VERSION 5.8 ;
BUSBITCHARS "[]" ;
DIVIDERCHAR "/" ;
UNITS
    DATABASE MICRONS 1000 ;
END UNITS

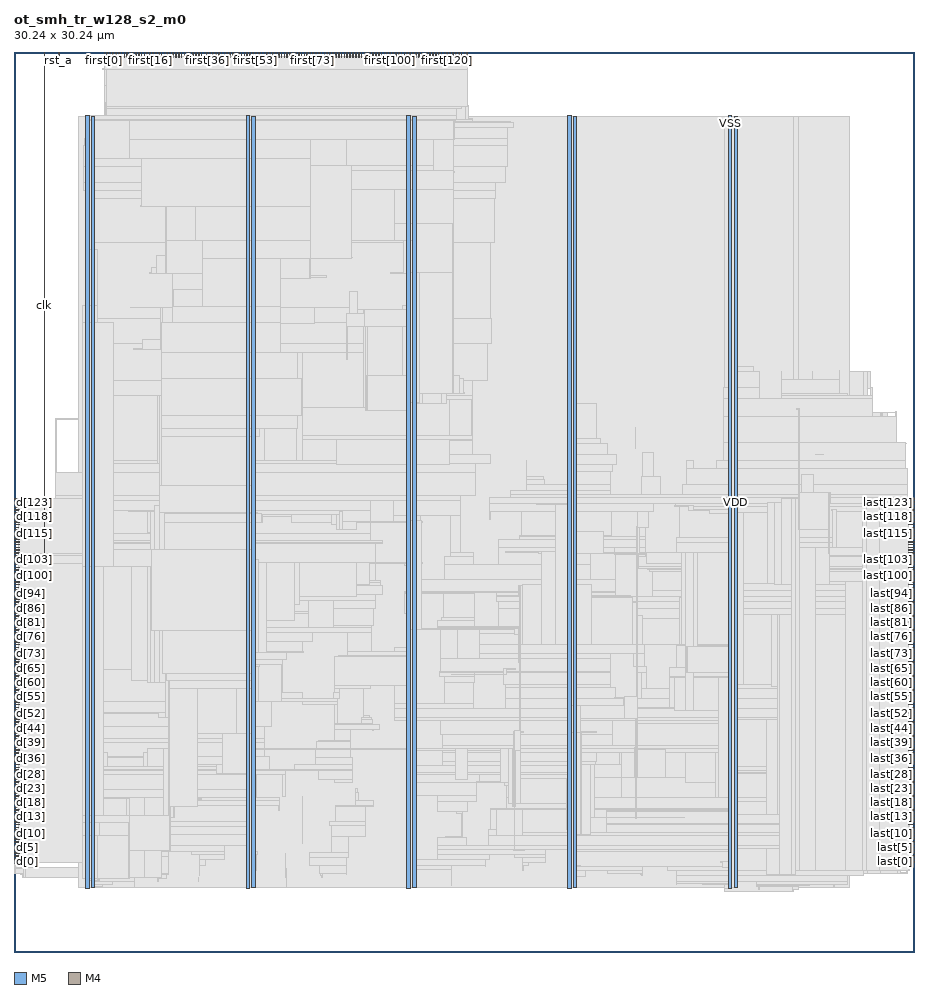
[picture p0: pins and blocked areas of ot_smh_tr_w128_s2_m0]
MACRO ot_smh_tr_w128_s2_m0
  FOREIGN ot_smh_tr_w128_s2_m0 0 0 ;
  CLASS BLOCK ;
  SIZE 30.24 BY 30.24 ;
  PIN clk
    DIRECTION INPUT ;
    USE SIGNAL ;
    PORT
      LAYER M5 ;
        RECT  1.008 30.048 1.032 30.24 ;
    END
    PORT
      LAYER M5 ;
        RECT  1.008 13.379 1.032 30.096 ;
    END
  END clk
  PIN d[0]
    DIRECTION INPUT ;
    USE SIGNAL ;
    PORT
      LAYER M4 ;
        RECT  0 3.024 0.192 3.048 ;
    END
  END d[0]
  PIN d[100]
    DIRECTION INPUT ;
    USE SIGNAL ;
    PORT
      LAYER M4 ;
        RECT  0 12.624 0.192 12.648 ;
    END
  END d[100]
  PIN d[101]
    DIRECTION INPUT ;
    USE SIGNAL ;
    PORT
      LAYER M4 ;
        RECT  0 12.72 0.192 12.744 ;
    END
  END d[101]
  PIN d[102]
    DIRECTION INPUT ;
    USE SIGNAL ;
    PORT
      LAYER M4 ;
        RECT  0 12.816 0.192 12.84 ;
    END
  END d[102]
  PIN d[103]
    DIRECTION INPUT ;
    USE SIGNAL ;
    PORT
      LAYER M4 ;
        RECT  0 12.912 0.192 12.936 ;
    END
  END d[103]
  PIN d[104]
    DIRECTION INPUT ;
    USE SIGNAL ;
    PORT
      LAYER M4 ;
        RECT  0 13.008 0.192 13.032 ;
    END
  END d[104]
  PIN d[105]
    DIRECTION INPUT ;
    USE SIGNAL ;
    PORT
      LAYER M4 ;
        RECT  0 13.104 0.192 13.128 ;
    END
  END d[105]
  PIN d[106]
    DIRECTION INPUT ;
    USE SIGNAL ;
    PORT
      LAYER M4 ;
        RECT  0 13.2 0.192 13.224 ;
    END
  END d[106]
  PIN d[107]
    DIRECTION INPUT ;
    USE SIGNAL ;
    PORT
      LAYER M4 ;
        RECT  0 13.296 0.192 13.32 ;
    END
  END d[107]
  PIN d[108]
    DIRECTION INPUT ;
    USE SIGNAL ;
    PORT
      LAYER M4 ;
        RECT  0 13.392 0.192 13.416 ;
    END
  END d[108]
  PIN d[109]
    DIRECTION INPUT ;
    USE SIGNAL ;
    PORT
      LAYER M4 ;
        RECT  0 13.488 0.192 13.512 ;
    END
  END d[109]
  PIN d[10]
    DIRECTION INPUT ;
    USE SIGNAL ;
    PORT
      LAYER M4 ;
        RECT  0 3.984 0.192 4.008 ;
    END
  END d[10]
  PIN d[110]
    DIRECTION INPUT ;
    USE SIGNAL ;
    PORT
      LAYER M4 ;
        RECT  0 13.584 0.192 13.608 ;
    END
  END d[110]
  PIN d[111]
    DIRECTION INPUT ;
    USE SIGNAL ;
    PORT
      LAYER M4 ;
        RECT  0 13.68 0.192 13.704 ;
    END
  END d[111]
  PIN d[112]
    DIRECTION INPUT ;
    USE SIGNAL ;
    PORT
      LAYER M4 ;
        RECT  0 13.776 0.192 13.8 ;
    END
  END d[112]
  PIN d[113]
    DIRECTION INPUT ;
    USE SIGNAL ;
    PORT
      LAYER M4 ;
        RECT  0 13.872 0.192 13.896 ;
    END
  END d[113]
  PIN d[114]
    DIRECTION INPUT ;
    USE SIGNAL ;
    PORT
      LAYER M4 ;
        RECT  0 13.968 0.192 13.992 ;
    END
  END d[114]
  PIN d[115]
    DIRECTION INPUT ;
    USE SIGNAL ;
    PORT
      LAYER M4 ;
        RECT  0 14.064 0.192 14.088 ;
    END
  END d[115]
  PIN d[116]
    DIRECTION INPUT ;
    USE SIGNAL ;
    PORT
      LAYER M4 ;
        RECT  0 14.16 0.192 14.184 ;
    END
  END d[116]
  PIN d[117]
    DIRECTION INPUT ;
    USE SIGNAL ;
    PORT
      LAYER M4 ;
        RECT  0 14.256 0.192 14.28 ;
    END
  END d[117]
  PIN d[118]
    DIRECTION INPUT ;
    USE SIGNAL ;
    PORT
      LAYER M4 ;
        RECT  0 14.352 0.192 14.376 ;
    END
  END d[118]
  PIN d[119]
    DIRECTION INPUT ;
    USE SIGNAL ;
    PORT
      LAYER M4 ;
        RECT  0 14.448 0.192 14.472 ;
    END
  END d[119]
  PIN d[11]
    DIRECTION INPUT ;
    USE SIGNAL ;
    PORT
      LAYER M4 ;
        RECT  0 4.08 0.192 4.104 ;
    END
  END d[11]
  PIN d[120]
    DIRECTION INPUT ;
    USE SIGNAL ;
    PORT
      LAYER M4 ;
        RECT  0 14.544 0.192 14.568 ;
    END
  END d[120]
  PIN d[121]
    DIRECTION INPUT ;
    USE SIGNAL ;
    PORT
      LAYER M4 ;
        RECT  0 14.64 0.192 14.664 ;
    END
  END d[121]
  PIN d[122]
    DIRECTION INPUT ;
    USE SIGNAL ;
    PORT
      LAYER M4 ;
        RECT  0 14.736 0.192 14.76 ;
    END
  END d[122]
  PIN d[123]
    DIRECTION INPUT ;
    USE SIGNAL ;
    PORT
      LAYER M4 ;
        RECT  0 14.832 0.192 14.856 ;
    END
  END d[123]
  PIN d[124]
    DIRECTION INPUT ;
    USE SIGNAL ;
    PORT
      LAYER M4 ;
        RECT  0 14.928 0.192 14.952 ;
    END
  END d[124]
  PIN d[125]
    DIRECTION INPUT ;
    USE SIGNAL ;
    PORT
      LAYER M4 ;
        RECT  0 15.024 0.192 15.048 ;
    END
  END d[125]
  PIN d[126]
    DIRECTION INPUT ;
    USE SIGNAL ;
    PORT
      LAYER M4 ;
        RECT  0 15.12 0.192 15.144 ;
    END
  END d[126]
  PIN d[127]
    DIRECTION INPUT ;
    USE SIGNAL ;
    PORT
      LAYER M4 ;
        RECT  0 15.216 0.192 15.24 ;
    END
  END d[127]
  PIN d[12]
    DIRECTION INPUT ;
    USE SIGNAL ;
    PORT
      LAYER M4 ;
        RECT  0 4.176 0.192 4.2 ;
    END
  END d[12]
  PIN d[13]
    DIRECTION INPUT ;
    USE SIGNAL ;
    PORT
      LAYER M4 ;
        RECT  0 4.272 0.192 4.296 ;
    END
  END d[13]
  PIN d[14]
    DIRECTION INPUT ;
    USE SIGNAL ;
    PORT
      LAYER M4 ;
        RECT  0 4.368 0.192 4.392 ;
    END
  END d[14]
  PIN d[15]
    DIRECTION INPUT ;
    USE SIGNAL ;
    PORT
      LAYER M4 ;
        RECT  0 4.464 0.192 4.488 ;
    END
  END d[15]
  PIN d[16]
    DIRECTION INPUT ;
    USE SIGNAL ;
    PORT
      LAYER M4 ;
        RECT  0 4.56 0.192 4.584 ;
    END
  END d[16]
  PIN d[17]
    DIRECTION INPUT ;
    USE SIGNAL ;
    PORT
      LAYER M4 ;
        RECT  0 4.656 0.192 4.68 ;
    END
  END d[17]
  PIN d[18]
    DIRECTION INPUT ;
    USE SIGNAL ;
    PORT
      LAYER M4 ;
        RECT  0 4.752 0.192 4.776 ;
    END
  END d[18]
  PIN d[19]
    DIRECTION INPUT ;
    USE SIGNAL ;
    PORT
      LAYER M4 ;
        RECT  0 4.848 0.192 4.872 ;
    END
  END d[19]
  PIN d[1]
    DIRECTION INPUT ;
    USE SIGNAL ;
    PORT
      LAYER M4 ;
        RECT  0 3.12 0.192 3.144 ;
    END
  END d[1]
  PIN d[20]
    DIRECTION INPUT ;
    USE SIGNAL ;
    PORT
      LAYER M4 ;
        RECT  0 4.944 0.192 4.968 ;
    END
  END d[20]
  PIN d[21]
    DIRECTION INPUT ;
    USE SIGNAL ;
    PORT
      LAYER M4 ;
        RECT  0 5.04 0.192 5.064 ;
    END
  END d[21]
  PIN d[22]
    DIRECTION INPUT ;
    USE SIGNAL ;
    PORT
      LAYER M4 ;
        RECT  0 5.136 0.192 5.16 ;
    END
  END d[22]
  PIN d[23]
    DIRECTION INPUT ;
    USE SIGNAL ;
    PORT
      LAYER M4 ;
        RECT  0 5.232 0.192 5.256 ;
    END
  END d[23]
  PIN d[24]
    DIRECTION INPUT ;
    USE SIGNAL ;
    PORT
      LAYER M4 ;
        RECT  0 5.328 0.192 5.352 ;
    END
  END d[24]
  PIN d[25]
    DIRECTION INPUT ;
    USE SIGNAL ;
    PORT
      LAYER M4 ;
        RECT  0 5.424 0.192 5.448 ;
    END
  END d[25]
  PIN d[26]
    DIRECTION INPUT ;
    USE SIGNAL ;
    PORT
      LAYER M4 ;
        RECT  0 5.52 0.192 5.544 ;
    END
  END d[26]
  PIN d[27]
    DIRECTION INPUT ;
    USE SIGNAL ;
    PORT
      LAYER M4 ;
        RECT  0 5.616 0.192 5.64 ;
    END
  END d[27]
  PIN d[28]
    DIRECTION INPUT ;
    USE SIGNAL ;
    PORT
      LAYER M4 ;
        RECT  0 5.712 0.192 5.736 ;
    END
  END d[28]
  PIN d[29]
    DIRECTION INPUT ;
    USE SIGNAL ;
    PORT
      LAYER M4 ;
        RECT  0 5.808 0.192 5.832 ;
    END
  END d[29]
  PIN d[2]
    DIRECTION INPUT ;
    USE SIGNAL ;
    PORT
      LAYER M4 ;
        RECT  0 3.216 0.192 3.24 ;
    END
  END d[2]
  PIN d[30]
    DIRECTION INPUT ;
    USE SIGNAL ;
    PORT
      LAYER M4 ;
        RECT  0 5.904 0.192 5.928 ;
    END
  END d[30]
  PIN d[31]
    DIRECTION INPUT ;
    USE SIGNAL ;
    PORT
      LAYER M4 ;
        RECT  0 6 0.192 6.024 ;
    END
  END d[31]
  PIN d[32]
    DIRECTION INPUT ;
    USE SIGNAL ;
    PORT
      LAYER M4 ;
        RECT  0 6.096 0.192 6.12 ;
    END
  END d[32]
  PIN d[33]
    DIRECTION INPUT ;
    USE SIGNAL ;
    PORT
      LAYER M4 ;
        RECT  0 6.192 0.192 6.216 ;
    END
  END d[33]
  PIN d[34]
    DIRECTION INPUT ;
    USE SIGNAL ;
    PORT
      LAYER M4 ;
        RECT  0 6.288 0.192 6.312 ;
    END
  END d[34]
  PIN d[35]
    DIRECTION INPUT ;
    USE SIGNAL ;
    PORT
      LAYER M4 ;
        RECT  0 6.384 0.192 6.408 ;
    END
  END d[35]
  PIN d[36]
    DIRECTION INPUT ;
    USE SIGNAL ;
    PORT
      LAYER M4 ;
        RECT  0 6.48 0.192 6.504 ;
    END
  END d[36]
  PIN d[37]
    DIRECTION INPUT ;
    USE SIGNAL ;
    PORT
      LAYER M4 ;
        RECT  0 6.576 0.192 6.6 ;
    END
  END d[37]
  PIN d[38]
    DIRECTION INPUT ;
    USE SIGNAL ;
    PORT
      LAYER M4 ;
        RECT  0 6.672 0.192 6.696 ;
    END
  END d[38]
  PIN d[39]
    DIRECTION INPUT ;
    USE SIGNAL ;
    PORT
      LAYER M4 ;
        RECT  0 6.768 0.192 6.792 ;
    END
  END d[39]
  PIN d[3]
    DIRECTION INPUT ;
    USE SIGNAL ;
    PORT
      LAYER M4 ;
        RECT  0 3.312 0.192 3.336 ;
    END
  END d[3]
  PIN d[40]
    DIRECTION INPUT ;
    USE SIGNAL ;
    PORT
      LAYER M4 ;
        RECT  0 6.864 0.192 6.888 ;
    END
  END d[40]
  PIN d[41]
    DIRECTION INPUT ;
    USE SIGNAL ;
    PORT
      LAYER M4 ;
        RECT  0 6.96 0.192 6.984 ;
    END
  END d[41]
  PIN d[42]
    DIRECTION INPUT ;
    USE SIGNAL ;
    PORT
      LAYER M4 ;
        RECT  0 7.056 0.192 7.08 ;
    END
  END d[42]
  PIN d[43]
    DIRECTION INPUT ;
    USE SIGNAL ;
    PORT
      LAYER M4 ;
        RECT  0 7.152 0.192 7.176 ;
    END
  END d[43]
  PIN d[44]
    DIRECTION INPUT ;
    USE SIGNAL ;
    PORT
      LAYER M4 ;
        RECT  0 7.248 0.192 7.272 ;
    END
  END d[44]
  PIN d[45]
    DIRECTION INPUT ;
    USE SIGNAL ;
    PORT
      LAYER M4 ;
        RECT  0 7.344 0.192 7.368 ;
    END
  END d[45]
  PIN d[46]
    DIRECTION INPUT ;
    USE SIGNAL ;
    PORT
      LAYER M4 ;
        RECT  0 7.44 0.192 7.464 ;
    END
  END d[46]
  PIN d[47]
    DIRECTION INPUT ;
    USE SIGNAL ;
    PORT
      LAYER M4 ;
        RECT  0 7.536 0.192 7.56 ;
    END
  END d[47]
  PIN d[48]
    DIRECTION INPUT ;
    USE SIGNAL ;
    PORT
      LAYER M4 ;
        RECT  0 7.632 0.192 7.656 ;
    END
  END d[48]
  PIN d[49]
    DIRECTION INPUT ;
    USE SIGNAL ;
    PORT
      LAYER M4 ;
        RECT  0 7.728 0.192 7.752 ;
    END
  END d[49]
  PIN d[4]
    DIRECTION INPUT ;
    USE SIGNAL ;
    PORT
      LAYER M4 ;
        RECT  0 3.408 0.192 3.432 ;
    END
  END d[4]
  PIN d[50]
    DIRECTION INPUT ;
    USE SIGNAL ;
    PORT
      LAYER M4 ;
        RECT  0 7.824 0.192 7.848 ;
    END
  END d[50]
  PIN d[51]
    DIRECTION INPUT ;
    USE SIGNAL ;
    PORT
      LAYER M4 ;
        RECT  0 7.92 0.192 7.944 ;
    END
  END d[51]
  PIN d[52]
    DIRECTION INPUT ;
    USE SIGNAL ;
    PORT
      LAYER M4 ;
        RECT  0 8.016 0.192 8.04 ;
    END
  END d[52]
  PIN d[53]
    DIRECTION INPUT ;
    USE SIGNAL ;
    PORT
      LAYER M4 ;
        RECT  0 8.112 0.192 8.136 ;
    END
  END d[53]
  PIN d[54]
    DIRECTION INPUT ;
    USE SIGNAL ;
    PORT
      LAYER M4 ;
        RECT  0 8.208 0.192 8.232 ;
    END
  END d[54]
  PIN d[55]
    DIRECTION INPUT ;
    USE SIGNAL ;
    PORT
      LAYER M4 ;
        RECT  0 8.304 0.192 8.328 ;
    END
  END d[55]
  PIN d[56]
    DIRECTION INPUT ;
    USE SIGNAL ;
    PORT
      LAYER M4 ;
        RECT  0 8.4 0.192 8.424 ;
    END
  END d[56]
  PIN d[57]
    DIRECTION INPUT ;
    USE SIGNAL ;
    PORT
      LAYER M4 ;
        RECT  0 8.496 0.192 8.52 ;
    END
  END d[57]
  PIN d[58]
    DIRECTION INPUT ;
    USE SIGNAL ;
    PORT
      LAYER M4 ;
        RECT  0 8.592 0.192 8.616 ;
    END
  END d[58]
  PIN d[59]
    DIRECTION INPUT ;
    USE SIGNAL ;
    PORT
      LAYER M4 ;
        RECT  0 8.688 0.192 8.712 ;
    END
  END d[59]
  PIN d[5]
    DIRECTION INPUT ;
    USE SIGNAL ;
    PORT
      LAYER M4 ;
        RECT  0 3.504 0.192 3.528 ;
    END
  END d[5]
  PIN d[60]
    DIRECTION INPUT ;
    USE SIGNAL ;
    PORT
      LAYER M4 ;
        RECT  0 8.784 0.192 8.808 ;
    END
  END d[60]
  PIN d[61]
    DIRECTION INPUT ;
    USE SIGNAL ;
    PORT
      LAYER M4 ;
        RECT  0 8.88 0.192 8.904 ;
    END
  END d[61]
  PIN d[62]
    DIRECTION INPUT ;
    USE SIGNAL ;
    PORT
      LAYER M4 ;
        RECT  0 8.976 0.192 9 ;
    END
  END d[62]
  PIN d[63]
    DIRECTION INPUT ;
    USE SIGNAL ;
    PORT
      LAYER M4 ;
        RECT  0 9.072 0.192 9.096 ;
    END
  END d[63]
  PIN d[64]
    DIRECTION INPUT ;
    USE SIGNAL ;
    PORT
      LAYER M4 ;
        RECT  0 9.168 0.192 9.192 ;
    END
  END d[64]
  PIN d[65]
    DIRECTION INPUT ;
    USE SIGNAL ;
    PORT
      LAYER M4 ;
        RECT  0 9.264 0.192 9.288 ;
    END
  END d[65]
  PIN d[66]
    DIRECTION INPUT ;
    USE SIGNAL ;
    PORT
      LAYER M4 ;
        RECT  0 9.36 0.192 9.384 ;
    END
  END d[66]
  PIN d[67]
    DIRECTION INPUT ;
    USE SIGNAL ;
    PORT
      LAYER M4 ;
        RECT  0 9.456 0.192 9.48 ;
    END
  END d[67]
  PIN d[68]
    DIRECTION INPUT ;
    USE SIGNAL ;
    PORT
      LAYER M4 ;
        RECT  0 9.552 0.192 9.576 ;
    END
  END d[68]
  PIN d[69]
    DIRECTION INPUT ;
    USE SIGNAL ;
    PORT
      LAYER M4 ;
        RECT  0 9.648 0.192 9.672 ;
    END
  END d[69]
  PIN d[6]
    DIRECTION INPUT ;
    USE SIGNAL ;
    PORT
      LAYER M4 ;
        RECT  0 3.6 0.192 3.624 ;
    END
  END d[6]
  PIN d[70]
    DIRECTION INPUT ;
    USE SIGNAL ;
    PORT
      LAYER M4 ;
        RECT  0 9.744 0.192 9.768 ;
    END
  END d[70]
  PIN d[71]
    DIRECTION INPUT ;
    USE SIGNAL ;
    PORT
      LAYER M4 ;
        RECT  0 9.84 0.192 9.864 ;
    END
  END d[71]
  PIN d[72]
    DIRECTION INPUT ;
    USE SIGNAL ;
    PORT
      LAYER M4 ;
        RECT  0 9.936 0.192 9.96 ;
    END
  END d[72]
  PIN d[73]
    DIRECTION INPUT ;
    USE SIGNAL ;
    PORT
      LAYER M4 ;
        RECT  0 10.032 0.192 10.056 ;
    END
  END d[73]
  PIN d[74]
    DIRECTION INPUT ;
    USE SIGNAL ;
    PORT
      LAYER M4 ;
        RECT  0 10.128 0.192 10.152 ;
    END
  END d[74]
  PIN d[75]
    DIRECTION INPUT ;
    USE SIGNAL ;
    PORT
      LAYER M4 ;
        RECT  0 10.224 0.192 10.248 ;
    END
  END d[75]
  PIN d[76]
    DIRECTION INPUT ;
    USE SIGNAL ;
    PORT
      LAYER M4 ;
        RECT  0 10.32 0.192 10.344 ;
    END
  END d[76]
  PIN d[77]
    DIRECTION INPUT ;
    USE SIGNAL ;
    PORT
      LAYER M4 ;
        RECT  0 10.416 0.192 10.44 ;
    END
  END d[77]
  PIN d[78]
    DIRECTION INPUT ;
    USE SIGNAL ;
    PORT
      LAYER M4 ;
        RECT  0 10.512 0.192 10.536 ;
    END
  END d[78]
  PIN d[79]
    DIRECTION INPUT ;
    USE SIGNAL ;
    PORT
      LAYER M4 ;
        RECT  0 10.608 0.192 10.632 ;
    END
  END d[79]
  PIN d[7]
    DIRECTION INPUT ;
    USE SIGNAL ;
    PORT
      LAYER M4 ;
        RECT  0 3.696 0.192 3.72 ;
    END
  END d[7]
  PIN d[80]
    DIRECTION INPUT ;
    USE SIGNAL ;
    PORT
      LAYER M4 ;
        RECT  0 10.704 0.192 10.728 ;
    END
  END d[80]
  PIN d[81]
    DIRECTION INPUT ;
    USE SIGNAL ;
    PORT
      LAYER M4 ;
        RECT  0 10.8 0.192 10.824 ;
    END
  END d[81]
  PIN d[82]
    DIRECTION INPUT ;
    USE SIGNAL ;
    PORT
      LAYER M4 ;
        RECT  0 10.896 0.192 10.92 ;
    END
  END d[82]
  PIN d[83]
    DIRECTION INPUT ;
    USE SIGNAL ;
    PORT
      LAYER M4 ;
        RECT  0 10.992 0.192 11.016 ;
    END
  END d[83]
  PIN d[84]
    DIRECTION INPUT ;
    USE SIGNAL ;
    PORT
      LAYER M4 ;
        RECT  0 11.088 0.192 11.112 ;
    END
  END d[84]
  PIN d[85]
    DIRECTION INPUT ;
    USE SIGNAL ;
    PORT
      LAYER M4 ;
        RECT  0 11.184 0.192 11.208 ;
    END
  END d[85]
  PIN d[86]
    DIRECTION INPUT ;
    USE SIGNAL ;
    PORT
      LAYER M4 ;
        RECT  0 11.28 0.192 11.304 ;
    END
  END d[86]
  PIN d[87]
    DIRECTION INPUT ;
    USE SIGNAL ;
    PORT
      LAYER M4 ;
        RECT  0 11.376 0.192 11.4 ;
    END
  END d[87]
  PIN d[88]
    DIRECTION INPUT ;
    USE SIGNAL ;
    PORT
      LAYER M4 ;
        RECT  0 11.472 0.192 11.496 ;
    END
  END d[88]
  PIN d[89]
    DIRECTION INPUT ;
    USE SIGNAL ;
    PORT
      LAYER M4 ;
        RECT  0 11.568 0.192 11.592 ;
    END
  END d[89]
  PIN d[8]
    DIRECTION INPUT ;
    USE SIGNAL ;
    PORT
      LAYER M4 ;
        RECT  0 3.792 0.192 3.816 ;
    END
  END d[8]
  PIN d[90]
    DIRECTION INPUT ;
    USE SIGNAL ;
    PORT
      LAYER M4 ;
        RECT  0 11.664 0.192 11.688 ;
    END
  END d[90]
  PIN d[91]
    DIRECTION INPUT ;
    USE SIGNAL ;
    PORT
      LAYER M4 ;
        RECT  0 11.76 0.192 11.784 ;
    END
  END d[91]
  PIN d[92]
    DIRECTION INPUT ;
    USE SIGNAL ;
    PORT
      LAYER M4 ;
        RECT  0 11.856 0.192 11.88 ;
    END
  END d[92]
  PIN d[93]
    DIRECTION INPUT ;
    USE SIGNAL ;
    PORT
      LAYER M4 ;
        RECT  0 11.952 0.192 11.976 ;
    END
  END d[93]
  PIN d[94]
    DIRECTION INPUT ;
    USE SIGNAL ;
    PORT
      LAYER M4 ;
        RECT  0 12.048 0.192 12.072 ;
    END
  END d[94]
  PIN d[95]
    DIRECTION INPUT ;
    USE SIGNAL ;
    PORT
      LAYER M4 ;
        RECT  0 12.144 0.192 12.168 ;
    END
  END d[95]
  PIN d[96]
    DIRECTION INPUT ;
    USE SIGNAL ;
    PORT
      LAYER M4 ;
        RECT  0 12.24 0.192 12.264 ;
    END
  END d[96]
  PIN d[97]
    DIRECTION INPUT ;
    USE SIGNAL ;
    PORT
      LAYER M4 ;
        RECT  0 12.336 0.192 12.36 ;
    END
  END d[97]
  PIN d[98]
    DIRECTION INPUT ;
    USE SIGNAL ;
    PORT
      LAYER M4 ;
        RECT  0 12.432 0.192 12.456 ;
    END
  END d[98]
  PIN d[99]
    DIRECTION INPUT ;
    USE SIGNAL ;
    PORT
      LAYER M4 ;
        RECT  0 12.528 0.192 12.552 ;
    END
  END d[99]
  PIN d[9]
    DIRECTION INPUT ;
    USE SIGNAL ;
    PORT
      LAYER M4 ;
        RECT  0 3.888 0.192 3.912 ;
    END
  END d[9]
  PIN first[0]
    DIRECTION OUTPUT ;
    USE SIGNAL ;
    PORT
      LAYER M5 ;
        RECT  3.024 30.048 3.048 30.24 ;
    END
  END first[0]
  PIN first[100]
    DIRECTION OUTPUT ;
    USE SIGNAL ;
    PORT
      LAYER M5 ;
        RECT  12.624 30.048 12.648 30.24 ;
    END
  END first[100]
  PIN first[101]
    DIRECTION OUTPUT ;
    USE SIGNAL ;
    PORT
      LAYER M5 ;
        RECT  12.72 30.048 12.744 30.24 ;
    END
  END first[101]
  PIN first[102]
    DIRECTION OUTPUT ;
    USE SIGNAL ;
    PORT
      LAYER M5 ;
        RECT  12.816 30.048 12.84 30.24 ;
    END
  END first[102]
  PIN first[103]
    DIRECTION OUTPUT ;
    USE SIGNAL ;
    PORT
      LAYER M5 ;
        RECT  12.912 30.048 12.936 30.24 ;
    END
  END first[103]
  PIN first[104]
    DIRECTION OUTPUT ;
    USE SIGNAL ;
    PORT
      LAYER M5 ;
        RECT  13.008 30.048 13.032 30.24 ;
    END
  END first[104]
  PIN first[105]
    DIRECTION OUTPUT ;
    USE SIGNAL ;
    PORT
      LAYER M5 ;
        RECT  13.104 30.048 13.128 30.24 ;
    END
  END first[105]
  PIN first[106]
    DIRECTION OUTPUT ;
    USE SIGNAL ;
    PORT
      LAYER M5 ;
        RECT  13.2 30.048 13.224 30.24 ;
    END
  END first[106]
  PIN first[107]
    DIRECTION OUTPUT ;
    USE SIGNAL ;
    PORT
      LAYER M5 ;
        RECT  13.296 30.048 13.32 30.24 ;
    END
  END first[107]
  PIN first[108]
    DIRECTION OUTPUT ;
    USE SIGNAL ;
    PORT
      LAYER M5 ;
        RECT  13.392 30.048 13.416 30.24 ;
    END
  END first[108]
  PIN first[109]
    DIRECTION OUTPUT ;
    USE SIGNAL ;
    PORT
      LAYER M5 ;
        RECT  13.488 30.048 13.512 30.24 ;
    END
  END first[109]
  PIN first[10]
    DIRECTION OUTPUT ;
    USE SIGNAL ;
    PORT
      LAYER M5 ;
        RECT  3.984 30.048 4.008 30.24 ;
    END
  END first[10]
  PIN first[110]
    DIRECTION OUTPUT ;
    USE SIGNAL ;
    PORT
      LAYER M5 ;
        RECT  13.584 30.048 13.608 30.24 ;
    END
  END first[110]
  PIN first[111]
    DIRECTION OUTPUT ;
    USE SIGNAL ;
    PORT
      LAYER M5 ;
        RECT  13.68 30.048 13.704 30.24 ;
    END
  END first[111]
  PIN first[112]
    DIRECTION OUTPUT ;
    USE SIGNAL ;
    PORT
      LAYER M5 ;
        RECT  13.776 30.048 13.8 30.24 ;
    END
  END first[112]
  PIN first[113]
    DIRECTION OUTPUT ;
    USE SIGNAL ;
    PORT
      LAYER M5 ;
        RECT  13.872 30.048 13.896 30.24 ;
    END
  END first[113]
  PIN first[114]
    DIRECTION OUTPUT ;
    USE SIGNAL ;
    PORT
      LAYER M5 ;
        RECT  13.968 30.048 13.992 30.24 ;
    END
  END first[114]
  PIN first[115]
    DIRECTION OUTPUT ;
    USE SIGNAL ;
    PORT
      LAYER M5 ;
        RECT  14.064 30.048 14.088 30.24 ;
    END
  END first[115]
  PIN first[116]
    DIRECTION OUTPUT ;
    USE SIGNAL ;
    PORT
      LAYER M5 ;
        RECT  14.16 30.048 14.184 30.24 ;
    END
  END first[116]
  PIN first[117]
    DIRECTION OUTPUT ;
    USE SIGNAL ;
    PORT
      LAYER M5 ;
        RECT  14.256 30.048 14.28 30.24 ;
    END
  END first[117]
  PIN first[118]
    DIRECTION OUTPUT ;
    USE SIGNAL ;
    PORT
      LAYER M5 ;
        RECT  14.352 30.048 14.376 30.24 ;
    END
  END first[118]
  PIN first[119]
    DIRECTION OUTPUT ;
    USE SIGNAL ;
    PORT
      LAYER M5 ;
        RECT  14.448 30.048 14.472 30.24 ;
    END
  END first[119]
  PIN first[11]
    DIRECTION OUTPUT ;
    USE SIGNAL ;
    PORT
      LAYER M5 ;
        RECT  4.08 30.048 4.104 30.24 ;
    END
  END first[11]
  PIN first[120]
    DIRECTION OUTPUT ;
    USE SIGNAL ;
    PORT
      LAYER M5 ;
        RECT  14.544 30.048 14.568 30.24 ;
    END
  END first[120]
  PIN first[121]
    DIRECTION OUTPUT ;
    USE SIGNAL ;
    PORT
      LAYER M5 ;
        RECT  14.64 30.048 14.664 30.24 ;
    END
  END first[121]
  PIN first[122]
    DIRECTION OUTPUT ;
    USE SIGNAL ;
    PORT
      LAYER M5 ;
        RECT  14.736 30.048 14.76 30.24 ;
    END
  END first[122]
  PIN first[123]
    DIRECTION OUTPUT ;
    USE SIGNAL ;
    PORT
      LAYER M5 ;
        RECT  14.832 30.048 14.856 30.24 ;
    END
  END first[123]
  PIN first[124]
    DIRECTION OUTPUT ;
    USE SIGNAL ;
    PORT
      LAYER M5 ;
        RECT  14.928 30.048 14.952 30.24 ;
    END
  END first[124]
  PIN first[125]
    DIRECTION OUTPUT ;
    USE SIGNAL ;
    PORT
      LAYER M5 ;
        RECT  15.024 30.048 15.048 30.24 ;
    END
  END first[125]
  PIN first[126]
    DIRECTION OUTPUT ;
    USE SIGNAL ;
    PORT
      LAYER M5 ;
        RECT  15.12 30.048 15.144 30.24 ;
    END
  END first[126]
  PIN first[127]
    DIRECTION OUTPUT ;
    USE SIGNAL ;
    PORT
      LAYER M5 ;
        RECT  15.216 30.048 15.24 30.24 ;
    END
  END first[127]
  PIN first[12]
    DIRECTION OUTPUT ;
    USE SIGNAL ;
    PORT
      LAYER M5 ;
        RECT  4.176 30.048 4.2 30.24 ;
    END
  END first[12]
  PIN first[13]
    DIRECTION OUTPUT ;
    USE SIGNAL ;
    PORT
      LAYER M5 ;
        RECT  4.272 30.048 4.296 30.24 ;
    END
  END first[13]
  PIN first[14]
    DIRECTION OUTPUT ;
    USE SIGNAL ;
    PORT
      LAYER M5 ;
        RECT  4.368 30.048 4.392 30.24 ;
    END
  END first[14]
  PIN first[15]
    DIRECTION OUTPUT ;
    USE SIGNAL ;
    PORT
      LAYER M5 ;
        RECT  4.464 30.048 4.488 30.24 ;
    END
  END first[15]
  PIN first[16]
    DIRECTION OUTPUT ;
    USE SIGNAL ;
    PORT
      LAYER M5 ;
        RECT  4.56 30.048 4.584 30.24 ;
    END
  END first[16]
  PIN first[17]
    DIRECTION OUTPUT ;
    USE SIGNAL ;
    PORT
      LAYER M5 ;
        RECT  4.656 30.048 4.68 30.24 ;
    END
  END first[17]
  PIN first[18]
    DIRECTION OUTPUT ;
    USE SIGNAL ;
    PORT
      LAYER M5 ;
        RECT  4.752 30.048 4.776 30.24 ;
    END
  END first[18]
  PIN first[19]
    DIRECTION OUTPUT ;
    USE SIGNAL ;
    PORT
      LAYER M5 ;
        RECT  4.848 30.048 4.872 30.24 ;
    END
  END first[19]
  PIN first[1]
    DIRECTION OUTPUT ;
    USE SIGNAL ;
    PORT
      LAYER M5 ;
        RECT  3.12 30.048 3.144 30.24 ;
    END
  END first[1]
  PIN first[20]
    DIRECTION OUTPUT ;
    USE SIGNAL ;
    PORT
      LAYER M5 ;
        RECT  4.944 30.048 4.968 30.24 ;
    END
  END first[20]
  PIN first[21]
    DIRECTION OUTPUT ;
    USE SIGNAL ;
    PORT
      LAYER M5 ;
        RECT  5.04 30.048 5.064 30.24 ;
    END
  END first[21]
  PIN first[22]
    DIRECTION OUTPUT ;
    USE SIGNAL ;
    PORT
      LAYER M5 ;
        RECT  5.136 30.048 5.16 30.24 ;
    END
  END first[22]
  PIN first[23]
    DIRECTION OUTPUT ;
    USE SIGNAL ;
    PORT
      LAYER M5 ;
        RECT  5.232 30.048 5.256 30.24 ;
    END
  END first[23]
  PIN first[24]
    DIRECTION OUTPUT ;
    USE SIGNAL ;
    PORT
      LAYER M5 ;
        RECT  5.328 30.048 5.352 30.24 ;
    END
  END first[24]
  PIN first[25]
    DIRECTION OUTPUT ;
    USE SIGNAL ;
    PORT
      LAYER M5 ;
        RECT  5.424 30.048 5.448 30.24 ;
    END
  END first[25]
  PIN first[26]
    DIRECTION OUTPUT ;
    USE SIGNAL ;
    PORT
      LAYER M5 ;
        RECT  5.52 30.048 5.544 30.24 ;
    END
  END first[26]
  PIN first[27]
    DIRECTION OUTPUT ;
    USE SIGNAL ;
    PORT
      LAYER M5 ;
        RECT  5.616 30.048 5.64 30.24 ;
    END
  END first[27]
  PIN first[28]
    DIRECTION OUTPUT ;
    USE SIGNAL ;
    PORT
      LAYER M5 ;
        RECT  5.712 30.048 5.736 30.24 ;
    END
  END first[28]
  PIN first[29]
    DIRECTION OUTPUT ;
    USE SIGNAL ;
    PORT
      LAYER M5 ;
        RECT  5.808 30.048 5.832 30.24 ;
    END
  END first[29]
  PIN first[2]
    DIRECTION OUTPUT ;
    USE SIGNAL ;
    PORT
      LAYER M5 ;
        RECT  3.216 30.048 3.24 30.24 ;
    END
  END first[2]
  PIN first[30]
    DIRECTION OUTPUT ;
    USE SIGNAL ;
    PORT
      LAYER M5 ;
        RECT  5.904 30.048 5.928 30.24 ;
    END
  END first[30]
  PIN first[31]
    DIRECTION OUTPUT ;
    USE SIGNAL ;
    PORT
      LAYER M5 ;
        RECT  6 30.048 6.024 30.24 ;
    END
  END first[31]
  PIN first[32]
    DIRECTION OUTPUT ;
    USE SIGNAL ;
    PORT
      LAYER M5 ;
        RECT  6.096 30.048 6.12 30.24 ;
    END
  END first[32]
  PIN first[33]
    DIRECTION OUTPUT ;
    USE SIGNAL ;
    PORT
      LAYER M5 ;
        RECT  6.192 30.048 6.216 30.24 ;
    END
  END first[33]
  PIN first[34]
    DIRECTION OUTPUT ;
    USE SIGNAL ;
    PORT
      LAYER M5 ;
        RECT  6.288 30.048 6.312 30.24 ;
    END
  END first[34]
  PIN first[35]
    DIRECTION OUTPUT ;
    USE SIGNAL ;
    PORT
      LAYER M5 ;
        RECT  6.384 30.048 6.408 30.24 ;
    END
  END first[35]
  PIN first[36]
    DIRECTION OUTPUT ;
    USE SIGNAL ;
    PORT
      LAYER M5 ;
        RECT  6.48 30.048 6.504 30.24 ;
    END
  END first[36]
  PIN first[37]
    DIRECTION OUTPUT ;
    USE SIGNAL ;
    PORT
      LAYER M5 ;
        RECT  6.576 30.048 6.6 30.24 ;
    END
  END first[37]
  PIN first[38]
    DIRECTION OUTPUT ;
    USE SIGNAL ;
    PORT
      LAYER M5 ;
        RECT  6.672 30.048 6.696 30.24 ;
    END
  END first[38]
  PIN first[39]
    DIRECTION OUTPUT ;
    USE SIGNAL ;
    PORT
      LAYER M5 ;
        RECT  6.768 30.048 6.792 30.24 ;
    END
  END first[39]
  PIN first[3]
    DIRECTION OUTPUT ;
    USE SIGNAL ;
    PORT
      LAYER M5 ;
        RECT  3.312 30.048 3.336 30.24 ;
    END
  END first[3]
  PIN first[40]
    DIRECTION OUTPUT ;
    USE SIGNAL ;
    PORT
      LAYER M5 ;
        RECT  6.864 30.048 6.888 30.24 ;
    END
  END first[40]
  PIN first[41]
    DIRECTION OUTPUT ;
    USE SIGNAL ;
    PORT
      LAYER M5 ;
        RECT  6.96 30.048 6.984 30.24 ;
    END
  END first[41]
  PIN first[42]
    DIRECTION OUTPUT ;
    USE SIGNAL ;
    PORT
      LAYER M5 ;
        RECT  7.056 30.048 7.08 30.24 ;
    END
  END first[42]
  PIN first[43]
    DIRECTION OUTPUT ;
    USE SIGNAL ;
    PORT
      LAYER M5 ;
        RECT  7.152 30.048 7.176 30.24 ;
    END
  END first[43]
  PIN first[44]
    DIRECTION OUTPUT ;
    USE SIGNAL ;
    PORT
      LAYER M5 ;
        RECT  7.248 30.048 7.272 30.24 ;
    END
  END first[44]
  PIN first[45]
    DIRECTION OUTPUT ;
    USE SIGNAL ;
    PORT
      LAYER M5 ;
        RECT  7.344 30.048 7.368 30.24 ;
    END
  END first[45]
  PIN first[46]
    DIRECTION OUTPUT ;
    USE SIGNAL ;
    PORT
      LAYER M5 ;
        RECT  7.44 30.048 7.464 30.24 ;
    END
  END first[46]
  PIN first[47]
    DIRECTION OUTPUT ;
    USE SIGNAL ;
    PORT
      LAYER M5 ;
        RECT  7.536 30.048 7.56 30.24 ;
    END
  END first[47]
  PIN first[48]
    DIRECTION OUTPUT ;
    USE SIGNAL ;
    PORT
      LAYER M5 ;
        RECT  7.632 30.048 7.656 30.24 ;
    END
  END first[48]
  PIN first[49]
    DIRECTION OUTPUT ;
    USE SIGNAL ;
    PORT
      LAYER M5 ;
        RECT  7.728 30.048 7.752 30.24 ;
    END
  END first[49]
  PIN first[4]
    DIRECTION OUTPUT ;
    USE SIGNAL ;
    PORT
      LAYER M5 ;
        RECT  3.408 30.048 3.432 30.24 ;
    END
  END first[4]
  PIN first[50]
    DIRECTION OUTPUT ;
    USE SIGNAL ;
    PORT
      LAYER M5 ;
        RECT  7.824 30.048 7.848 30.24 ;
    END
  END first[50]
  PIN first[51]
    DIRECTION OUTPUT ;
    USE SIGNAL ;
    PORT
      LAYER M5 ;
        RECT  7.92 30.048 7.944 30.24 ;
    END
  END first[51]
  PIN first[52]
    DIRECTION OUTPUT ;
    USE SIGNAL ;
    PORT
      LAYER M5 ;
        RECT  8.016 30.048 8.04 30.24 ;
    END
  END first[52]
  PIN first[53]
    DIRECTION OUTPUT ;
    USE SIGNAL ;
    PORT
      LAYER M5 ;
        RECT  8.112 30.048 8.136 30.24 ;
    END
  END first[53]
  PIN first[54]
    DIRECTION OUTPUT ;
    USE SIGNAL ;
    PORT
      LAYER M5 ;
        RECT  8.208 30.048 8.232 30.24 ;
    END
  END first[54]
  PIN first[55]
    DIRECTION OUTPUT ;
    USE SIGNAL ;
    PORT
      LAYER M5 ;
        RECT  8.304 30.048 8.328 30.24 ;
    END
  END first[55]
  PIN first[56]
    DIRECTION OUTPUT ;
    USE SIGNAL ;
    PORT
      LAYER M5 ;
        RECT  8.4 30.048 8.424 30.24 ;
    END
  END first[56]
  PIN first[57]
    DIRECTION OUTPUT ;
    USE SIGNAL ;
    PORT
      LAYER M5 ;
        RECT  8.496 30.048 8.52 30.24 ;
    END
  END first[57]
  PIN first[58]
    DIRECTION OUTPUT ;
    USE SIGNAL ;
    PORT
      LAYER M5 ;
        RECT  8.592 30.048 8.616 30.24 ;
    END
  END first[58]
  PIN first[59]
    DIRECTION OUTPUT ;
    USE SIGNAL ;
    PORT
      LAYER M5 ;
        RECT  8.688 30.048 8.712 30.24 ;
    END
  END first[59]
  PIN first[5]
    DIRECTION OUTPUT ;
    USE SIGNAL ;
    PORT
      LAYER M5 ;
        RECT  3.504 30.048 3.528 30.24 ;
    END
  END first[5]
  PIN first[60]
    DIRECTION OUTPUT ;
    USE SIGNAL ;
    PORT
      LAYER M5 ;
        RECT  8.784 30.048 8.808 30.24 ;
    END
  END first[60]
  PIN first[61]
    DIRECTION OUTPUT ;
    USE SIGNAL ;
    PORT
      LAYER M5 ;
        RECT  8.88 30.048 8.904 30.24 ;
    END
  END first[61]
  PIN first[62]
    DIRECTION OUTPUT ;
    USE SIGNAL ;
    PORT
      LAYER M5 ;
        RECT  8.976 30.048 9 30.24 ;
    END
  END first[62]
  PIN first[63]
    DIRECTION OUTPUT ;
    USE SIGNAL ;
    PORT
      LAYER M5 ;
        RECT  9.072 30.048 9.096 30.24 ;
    END
  END first[63]
  PIN first[64]
    DIRECTION OUTPUT ;
    USE SIGNAL ;
    PORT
      LAYER M5 ;
        RECT  9.168 30.048 9.192 30.24 ;
    END
  END first[64]
  PIN first[65]
    DIRECTION OUTPUT ;
    USE SIGNAL ;
    PORT
      LAYER M5 ;
        RECT  9.264 30.048 9.288 30.24 ;
    END
  END first[65]
  PIN first[66]
    DIRECTION OUTPUT ;
    USE SIGNAL ;
    PORT
      LAYER M5 ;
        RECT  9.36 30.048 9.384 30.24 ;
    END
  END first[66]
  PIN first[67]
    DIRECTION OUTPUT ;
    USE SIGNAL ;
    PORT
      LAYER M5 ;
        RECT  9.456 30.048 9.48 30.24 ;
    END
  END first[67]
  PIN first[68]
    DIRECTION OUTPUT ;
    USE SIGNAL ;
    PORT
      LAYER M5 ;
        RECT  9.552 30.048 9.576 30.24 ;
    END
  END first[68]
  PIN first[69]
    DIRECTION OUTPUT ;
    USE SIGNAL ;
    PORT
      LAYER M5 ;
        RECT  9.648 30.048 9.672 30.24 ;
    END
  END first[69]
  PIN first[6]
    DIRECTION OUTPUT ;
    USE SIGNAL ;
    PORT
      LAYER M5 ;
        RECT  3.6 30.048 3.624 30.24 ;
    END
  END first[6]
  PIN first[70]
    DIRECTION OUTPUT ;
    USE SIGNAL ;
    PORT
      LAYER M5 ;
        RECT  9.744 30.048 9.768 30.24 ;
    END
  END first[70]
  PIN first[71]
    DIRECTION OUTPUT ;
    USE SIGNAL ;
    PORT
      LAYER M5 ;
        RECT  9.84 30.048 9.864 30.24 ;
    END
  END first[71]
  PIN first[72]
    DIRECTION OUTPUT ;
    USE SIGNAL ;
    PORT
      LAYER M5 ;
        RECT  9.936 30.048 9.96 30.24 ;
    END
  END first[72]
  PIN first[73]
    DIRECTION OUTPUT ;
    USE SIGNAL ;
    PORT
      LAYER M5 ;
        RECT  10.032 30.048 10.056 30.24 ;
    END
  END first[73]
  PIN first[74]
    DIRECTION OUTPUT ;
    USE SIGNAL ;
    PORT
      LAYER M5 ;
        RECT  10.128 30.048 10.152 30.24 ;
    END
  END first[74]
  PIN first[75]
    DIRECTION OUTPUT ;
    USE SIGNAL ;
    PORT
      LAYER M5 ;
        RECT  10.224 30.048 10.248 30.24 ;
    END
  END first[75]
  PIN first[76]
    DIRECTION OUTPUT ;
    USE SIGNAL ;
    PORT
      LAYER M5 ;
        RECT  10.32 30.048 10.344 30.24 ;
    END
  END first[76]
  PIN first[77]
    DIRECTION OUTPUT ;
    USE SIGNAL ;
    PORT
      LAYER M5 ;
        RECT  10.416 30.048 10.44 30.24 ;
    END
  END first[77]
  PIN first[78]
    DIRECTION OUTPUT ;
    USE SIGNAL ;
    PORT
      LAYER M5 ;
        RECT  10.512 30.048 10.536 30.24 ;
    END
  END first[78]
  PIN first[79]
    DIRECTION OUTPUT ;
    USE SIGNAL ;
    PORT
      LAYER M5 ;
        RECT  10.608 30.048 10.632 30.24 ;
    END
  END first[79]
  PIN first[7]
    DIRECTION OUTPUT ;
    USE SIGNAL ;
    PORT
      LAYER M5 ;
        RECT  3.696 30.048 3.72 30.24 ;
    END
  END first[7]
  PIN first[80]
    DIRECTION OUTPUT ;
    USE SIGNAL ;
    PORT
      LAYER M5 ;
        RECT  10.704 30.048 10.728 30.24 ;
    END
  END first[80]
  PIN first[81]
    DIRECTION OUTPUT ;
    USE SIGNAL ;
    PORT
      LAYER M5 ;
        RECT  10.8 30.048 10.824 30.24 ;
    END
  END first[81]
  PIN first[82]
    DIRECTION OUTPUT ;
    USE SIGNAL ;
    PORT
      LAYER M5 ;
        RECT  10.896 30.048 10.92 30.24 ;
    END
  END first[82]
  PIN first[83]
    DIRECTION OUTPUT ;
    USE SIGNAL ;
    PORT
      LAYER M5 ;
        RECT  10.992 30.048 11.016 30.24 ;
    END
  END first[83]
  PIN first[84]
    DIRECTION OUTPUT ;
    USE SIGNAL ;
    PORT
      LAYER M5 ;
        RECT  11.088 30.048 11.112 30.24 ;
    END
  END first[84]
  PIN first[85]
    DIRECTION OUTPUT ;
    USE SIGNAL ;
    PORT
      LAYER M5 ;
        RECT  11.184 30.048 11.208 30.24 ;
    END
  END first[85]
  PIN first[86]
    DIRECTION OUTPUT ;
    USE SIGNAL ;
    PORT
      LAYER M5 ;
        RECT  11.28 30.048 11.304 30.24 ;
    END
  END first[86]
  PIN first[87]
    DIRECTION OUTPUT ;
    USE SIGNAL ;
    PORT
      LAYER M5 ;
        RECT  11.376 30.048 11.4 30.24 ;
    END
  END first[87]
  PIN first[88]
    DIRECTION OUTPUT ;
    USE SIGNAL ;
    PORT
      LAYER M5 ;
        RECT  11.472 30.048 11.496 30.24 ;
    END
  END first[88]
  PIN first[89]
    DIRECTION OUTPUT ;
    USE SIGNAL ;
    PORT
      LAYER M5 ;
        RECT  11.568 30.048 11.592 30.24 ;
    END
  END first[89]
  PIN first[8]
    DIRECTION OUTPUT ;
    USE SIGNAL ;
    PORT
      LAYER M5 ;
        RECT  3.792 30.048 3.816 30.24 ;
    END
  END first[8]
  PIN first[90]
    DIRECTION OUTPUT ;
    USE SIGNAL ;
    PORT
      LAYER M5 ;
        RECT  11.664 30.048 11.688 30.24 ;
    END
  END first[90]
  PIN first[91]
    DIRECTION OUTPUT ;
    USE SIGNAL ;
    PORT
      LAYER M5 ;
        RECT  11.76 30.048 11.784 30.24 ;
    END
  END first[91]
  PIN first[92]
    DIRECTION OUTPUT ;
    USE SIGNAL ;
    PORT
      LAYER M5 ;
        RECT  11.856 30.048 11.88 30.24 ;
    END
  END first[92]
  PIN first[93]
    DIRECTION OUTPUT ;
    USE SIGNAL ;
    PORT
      LAYER M5 ;
        RECT  11.952 30.048 11.976 30.24 ;
    END
  END first[93]
  PIN first[94]
    DIRECTION OUTPUT ;
    USE SIGNAL ;
    PORT
      LAYER M5 ;
        RECT  12.048 30.048 12.072 30.24 ;
    END
  END first[94]
  PIN first[95]
    DIRECTION OUTPUT ;
    USE SIGNAL ;
    PORT
      LAYER M5 ;
        RECT  12.144 30.048 12.168 30.24 ;
    END
  END first[95]
  PIN first[96]
    DIRECTION OUTPUT ;
    USE SIGNAL ;
    PORT
      LAYER M5 ;
        RECT  12.24 30.048 12.264 30.24 ;
    END
  END first[96]
  PIN first[97]
    DIRECTION OUTPUT ;
    USE SIGNAL ;
    PORT
      LAYER M5 ;
        RECT  12.336 30.048 12.36 30.24 ;
    END
  END first[97]
  PIN first[98]
    DIRECTION OUTPUT ;
    USE SIGNAL ;
    PORT
      LAYER M5 ;
        RECT  12.432 30.048 12.456 30.24 ;
    END
  END first[98]
  PIN first[99]
    DIRECTION OUTPUT ;
    USE SIGNAL ;
    PORT
      LAYER M5 ;
        RECT  12.528 30.048 12.552 30.24 ;
    END
  END first[99]
  PIN first[9]
    DIRECTION OUTPUT ;
    USE SIGNAL ;
    PORT
      LAYER M5 ;
        RECT  3.888 30.048 3.912 30.24 ;
    END
  END first[9]
  PIN last[0]
    DIRECTION OUTPUT ;
    USE SIGNAL ;
    PORT
      LAYER M4 ;
        RECT  30.048 3.024 30.24 3.048 ;
    END
  END last[0]
  PIN last[100]
    DIRECTION OUTPUT ;
    USE SIGNAL ;
    PORT
      LAYER M4 ;
        RECT  30.048 12.624 30.24 12.648 ;
    END
  END last[100]
  PIN last[101]
    DIRECTION OUTPUT ;
    USE SIGNAL ;
    PORT
      LAYER M4 ;
        RECT  30.048 12.72 30.24 12.744 ;
    END
  END last[101]
  PIN last[102]
    DIRECTION OUTPUT ;
    USE SIGNAL ;
    PORT
      LAYER M4 ;
        RECT  30.048 12.816 30.24 12.84 ;
    END
  END last[102]
  PIN last[103]
    DIRECTION OUTPUT ;
    USE SIGNAL ;
    PORT
      LAYER M4 ;
        RECT  30.048 12.912 30.24 12.936 ;
    END
  END last[103]
  PIN last[104]
    DIRECTION OUTPUT ;
    USE SIGNAL ;
    PORT
      LAYER M4 ;
        RECT  30.048 13.008 30.24 13.032 ;
    END
  END last[104]
  PIN last[105]
    DIRECTION OUTPUT ;
    USE SIGNAL ;
    PORT
      LAYER M4 ;
        RECT  30.048 13.104 30.24 13.128 ;
    END
  END last[105]
  PIN last[106]
    DIRECTION OUTPUT ;
    USE SIGNAL ;
    PORT
      LAYER M4 ;
        RECT  30.048 13.2 30.24 13.224 ;
    END
  END last[106]
  PIN last[107]
    DIRECTION OUTPUT ;
    USE SIGNAL ;
    PORT
      LAYER M4 ;
        RECT  30.048 13.296 30.24 13.32 ;
    END
  END last[107]
  PIN last[108]
    DIRECTION OUTPUT ;
    USE SIGNAL ;
    PORT
      LAYER M4 ;
        RECT  30.048 13.392 30.24 13.416 ;
    END
  END last[108]
  PIN last[109]
    DIRECTION OUTPUT ;
    USE SIGNAL ;
    PORT
      LAYER M4 ;
        RECT  30.048 13.488 30.24 13.512 ;
    END
  END last[109]
  PIN last[10]
    DIRECTION OUTPUT ;
    USE SIGNAL ;
    PORT
      LAYER M4 ;
        RECT  30.048 3.984 30.24 4.008 ;
    END
  END last[10]
  PIN last[110]
    DIRECTION OUTPUT ;
    USE SIGNAL ;
    PORT
      LAYER M4 ;
        RECT  30.048 13.584 30.24 13.608 ;
    END
  END last[110]
  PIN last[111]
    DIRECTION OUTPUT ;
    USE SIGNAL ;
    PORT
      LAYER M4 ;
        RECT  30.048 13.68 30.24 13.704 ;
    END
  END last[111]
  PIN last[112]
    DIRECTION OUTPUT ;
    USE SIGNAL ;
    PORT
      LAYER M4 ;
        RECT  30.048 13.776 30.24 13.8 ;
    END
  END last[112]
  PIN last[113]
    DIRECTION OUTPUT ;
    USE SIGNAL ;
    PORT
      LAYER M4 ;
        RECT  30.048 13.872 30.24 13.896 ;
    END
  END last[113]
  PIN last[114]
    DIRECTION OUTPUT ;
    USE SIGNAL ;
    PORT
      LAYER M4 ;
        RECT  30.048 13.968 30.24 13.992 ;
    END
  END last[114]
  PIN last[115]
    DIRECTION OUTPUT ;
    USE SIGNAL ;
    PORT
      LAYER M4 ;
        RECT  30.048 14.064 30.24 14.088 ;
    END
  END last[115]
  PIN last[116]
    DIRECTION OUTPUT ;
    USE SIGNAL ;
    PORT
      LAYER M4 ;
        RECT  30.048 14.16 30.24 14.184 ;
    END
  END last[116]
  PIN last[117]
    DIRECTION OUTPUT ;
    USE SIGNAL ;
    PORT
      LAYER M4 ;
        RECT  30.048 14.256 30.24 14.28 ;
    END
  END last[117]
  PIN last[118]
    DIRECTION OUTPUT ;
    USE SIGNAL ;
    PORT
      LAYER M4 ;
        RECT  30.048 14.352 30.24 14.376 ;
    END
  END last[118]
  PIN last[119]
    DIRECTION OUTPUT ;
    USE SIGNAL ;
    PORT
      LAYER M4 ;
        RECT  30.048 14.448 30.24 14.472 ;
    END
  END last[119]
  PIN last[11]
    DIRECTION OUTPUT ;
    USE SIGNAL ;
    PORT
      LAYER M4 ;
        RECT  30.048 4.08 30.24 4.104 ;
    END
  END last[11]
  PIN last[120]
    DIRECTION OUTPUT ;
    USE SIGNAL ;
    PORT
      LAYER M4 ;
        RECT  30.048 14.544 30.24 14.568 ;
    END
  END last[120]
  PIN last[121]
    DIRECTION OUTPUT ;
    USE SIGNAL ;
    PORT
      LAYER M4 ;
        RECT  30.048 14.64 30.24 14.664 ;
    END
  END last[121]
  PIN last[122]
    DIRECTION OUTPUT ;
    USE SIGNAL ;
    PORT
      LAYER M4 ;
        RECT  30.048 14.736 30.24 14.76 ;
    END
  END last[122]
  PIN last[123]
    DIRECTION OUTPUT ;
    USE SIGNAL ;
    PORT
      LAYER M4 ;
        RECT  30.048 14.832 30.24 14.856 ;
    END
  END last[123]
  PIN last[124]
    DIRECTION OUTPUT ;
    USE SIGNAL ;
    PORT
      LAYER M4 ;
        RECT  30.048 14.928 30.24 14.952 ;
    END
  END last[124]
  PIN last[125]
    DIRECTION OUTPUT ;
    USE SIGNAL ;
    PORT
      LAYER M4 ;
        RECT  30.048 15.024 30.24 15.048 ;
    END
  END last[125]
  PIN last[126]
    DIRECTION OUTPUT ;
    USE SIGNAL ;
    PORT
      LAYER M4 ;
        RECT  30.048 15.12 30.24 15.144 ;
    END
  END last[126]
  PIN last[127]
    DIRECTION OUTPUT ;
    USE SIGNAL ;
    PORT
      LAYER M4 ;
        RECT  30.048 15.216 30.24 15.24 ;
    END
  END last[127]
  PIN last[12]
    DIRECTION OUTPUT ;
    USE SIGNAL ;
    PORT
      LAYER M4 ;
        RECT  30.048 4.176 30.24 4.2 ;
    END
  END last[12]
  PIN last[13]
    DIRECTION OUTPUT ;
    USE SIGNAL ;
    PORT
      LAYER M4 ;
        RECT  30.048 4.272 30.24 4.296 ;
    END
  END last[13]
  PIN last[14]
    DIRECTION OUTPUT ;
    USE SIGNAL ;
    PORT
      LAYER M4 ;
        RECT  30.048 4.368 30.24 4.392 ;
    END
  END last[14]
  PIN last[15]
    DIRECTION OUTPUT ;
    USE SIGNAL ;
    PORT
      LAYER M4 ;
        RECT  30.048 4.464 30.24 4.488 ;
    END
  END last[15]
  PIN last[16]
    DIRECTION OUTPUT ;
    USE SIGNAL ;
    PORT
      LAYER M4 ;
        RECT  30.048 4.56 30.24 4.584 ;
    END
  END last[16]
  PIN last[17]
    DIRECTION OUTPUT ;
    USE SIGNAL ;
    PORT
      LAYER M4 ;
        RECT  30.048 4.656 30.24 4.68 ;
    END
  END last[17]
  PIN last[18]
    DIRECTION OUTPUT ;
    USE SIGNAL ;
    PORT
      LAYER M4 ;
        RECT  30.048 4.752 30.24 4.776 ;
    END
  END last[18]
  PIN last[19]
    DIRECTION OUTPUT ;
    USE SIGNAL ;
    PORT
      LAYER M4 ;
        RECT  30.048 4.848 30.24 4.872 ;
    END
  END last[19]
  PIN last[1]
    DIRECTION OUTPUT ;
    USE SIGNAL ;
    PORT
      LAYER M4 ;
        RECT  30.048 3.12 30.24 3.144 ;
    END
  END last[1]
  PIN last[20]
    DIRECTION OUTPUT ;
    USE SIGNAL ;
    PORT
      LAYER M4 ;
        RECT  30.048 4.944 30.24 4.968 ;
    END
  END last[20]
  PIN last[21]
    DIRECTION OUTPUT ;
    USE SIGNAL ;
    PORT
      LAYER M4 ;
        RECT  30.048 5.04 30.24 5.064 ;
    END
  END last[21]
  PIN last[22]
    DIRECTION OUTPUT ;
    USE SIGNAL ;
    PORT
      LAYER M4 ;
        RECT  30.048 5.136 30.24 5.16 ;
    END
  END last[22]
  PIN last[23]
    DIRECTION OUTPUT ;
    USE SIGNAL ;
    PORT
      LAYER M4 ;
        RECT  30.048 5.232 30.24 5.256 ;
    END
  END last[23]
  PIN last[24]
    DIRECTION OUTPUT ;
    USE SIGNAL ;
    PORT
      LAYER M4 ;
        RECT  30.048 5.328 30.24 5.352 ;
    END
  END last[24]
  PIN last[25]
    DIRECTION OUTPUT ;
    USE SIGNAL ;
    PORT
      LAYER M4 ;
        RECT  30.048 5.424 30.24 5.448 ;
    END
  END last[25]
  PIN last[26]
    DIRECTION OUTPUT ;
    USE SIGNAL ;
    PORT
      LAYER M4 ;
        RECT  30.048 5.52 30.24 5.544 ;
    END
  END last[26]
  PIN last[27]
    DIRECTION OUTPUT ;
    USE SIGNAL ;
    PORT
      LAYER M4 ;
        RECT  30.048 5.616 30.24 5.64 ;
    END
  END last[27]
  PIN last[28]
    DIRECTION OUTPUT ;
    USE SIGNAL ;
    PORT
      LAYER M4 ;
        RECT  30.048 5.712 30.24 5.736 ;
    END
  END last[28]
  PIN last[29]
    DIRECTION OUTPUT ;
    USE SIGNAL ;
    PORT
      LAYER M4 ;
        RECT  30.048 5.808 30.24 5.832 ;
    END
  END last[29]
  PIN last[2]
    DIRECTION OUTPUT ;
    USE SIGNAL ;
    PORT
      LAYER M4 ;
        RECT  30.048 3.216 30.24 3.24 ;
    END
  END last[2]
  PIN last[30]
    DIRECTION OUTPUT ;
    USE SIGNAL ;
    PORT
      LAYER M4 ;
        RECT  30.048 5.904 30.24 5.928 ;
    END
  END last[30]
  PIN last[31]
    DIRECTION OUTPUT ;
    USE SIGNAL ;
    PORT
      LAYER M4 ;
        RECT  30.048 6 30.24 6.024 ;
    END
  END last[31]
  PIN last[32]
    DIRECTION OUTPUT ;
    USE SIGNAL ;
    PORT
      LAYER M4 ;
        RECT  30.048 6.096 30.24 6.12 ;
    END
  END last[32]
  PIN last[33]
    DIRECTION OUTPUT ;
    USE SIGNAL ;
    PORT
      LAYER M4 ;
        RECT  30.048 6.192 30.24 6.216 ;
    END
  END last[33]
  PIN last[34]
    DIRECTION OUTPUT ;
    USE SIGNAL ;
    PORT
      LAYER M4 ;
        RECT  30.048 6.288 30.24 6.312 ;
    END
  END last[34]
  PIN last[35]
    DIRECTION OUTPUT ;
    USE SIGNAL ;
    PORT
      LAYER M4 ;
        RECT  30.048 6.384 30.24 6.408 ;
    END
  END last[35]
  PIN last[36]
    DIRECTION OUTPUT ;
    USE SIGNAL ;
    PORT
      LAYER M4 ;
        RECT  30.048 6.48 30.24 6.504 ;
    END
  END last[36]
  PIN last[37]
    DIRECTION OUTPUT ;
    USE SIGNAL ;
    PORT
      LAYER M4 ;
        RECT  30.048 6.576 30.24 6.6 ;
    END
  END last[37]
  PIN last[38]
    DIRECTION OUTPUT ;
    USE SIGNAL ;
    PORT
      LAYER M4 ;
        RECT  30.048 6.672 30.24 6.696 ;
    END
  END last[38]
  PIN last[39]
    DIRECTION OUTPUT ;
    USE SIGNAL ;
    PORT
      LAYER M4 ;
        RECT  30.048 6.768 30.24 6.792 ;
    END
  END last[39]
  PIN last[3]
    DIRECTION OUTPUT ;
    USE SIGNAL ;
    PORT
      LAYER M4 ;
        RECT  30.048 3.312 30.24 3.336 ;
    END
  END last[3]
  PIN last[40]
    DIRECTION OUTPUT ;
    USE SIGNAL ;
    PORT
      LAYER M4 ;
        RECT  30.048 6.864 30.24 6.888 ;
    END
  END last[40]
  PIN last[41]
    DIRECTION OUTPUT ;
    USE SIGNAL ;
    PORT
      LAYER M4 ;
        RECT  30.048 6.96 30.24 6.984 ;
    END
  END last[41]
  PIN last[42]
    DIRECTION OUTPUT ;
    USE SIGNAL ;
    PORT
      LAYER M4 ;
        RECT  30.048 7.056 30.24 7.08 ;
    END
  END last[42]
  PIN last[43]
    DIRECTION OUTPUT ;
    USE SIGNAL ;
    PORT
      LAYER M4 ;
        RECT  30.048 7.152 30.24 7.176 ;
    END
  END last[43]
  PIN last[44]
    DIRECTION OUTPUT ;
    USE SIGNAL ;
    PORT
      LAYER M4 ;
        RECT  30.048 7.248 30.24 7.272 ;
    END
  END last[44]
  PIN last[45]
    DIRECTION OUTPUT ;
    USE SIGNAL ;
    PORT
      LAYER M4 ;
        RECT  30.048 7.344 30.24 7.368 ;
    END
  END last[45]
  PIN last[46]
    DIRECTION OUTPUT ;
    USE SIGNAL ;
    PORT
      LAYER M4 ;
        RECT  30.048 7.44 30.24 7.464 ;
    END
  END last[46]
  PIN last[47]
    DIRECTION OUTPUT ;
    USE SIGNAL ;
    PORT
      LAYER M4 ;
        RECT  30.048 7.536 30.24 7.56 ;
    END
  END last[47]
  PIN last[48]
    DIRECTION OUTPUT ;
    USE SIGNAL ;
    PORT
      LAYER M4 ;
        RECT  30.048 7.632 30.24 7.656 ;
    END
  END last[48]
  PIN last[49]
    DIRECTION OUTPUT ;
    USE SIGNAL ;
    PORT
      LAYER M4 ;
        RECT  30.048 7.728 30.24 7.752 ;
    END
  END last[49]
  PIN last[4]
    DIRECTION OUTPUT ;
    USE SIGNAL ;
    PORT
      LAYER M4 ;
        RECT  30.048 3.408 30.24 3.432 ;
    END
  END last[4]
  PIN last[50]
    DIRECTION OUTPUT ;
    USE SIGNAL ;
    PORT
      LAYER M4 ;
        RECT  30.048 7.824 30.24 7.848 ;
    END
  END last[50]
  PIN last[51]
    DIRECTION OUTPUT ;
    USE SIGNAL ;
    PORT
      LAYER M4 ;
        RECT  30.048 7.92 30.24 7.944 ;
    END
  END last[51]
  PIN last[52]
    DIRECTION OUTPUT ;
    USE SIGNAL ;
    PORT
      LAYER M4 ;
        RECT  30.048 8.016 30.24 8.04 ;
    END
  END last[52]
  PIN last[53]
    DIRECTION OUTPUT ;
    USE SIGNAL ;
    PORT
      LAYER M4 ;
        RECT  30.048 8.112 30.24 8.136 ;
    END
  END last[53]
  PIN last[54]
    DIRECTION OUTPUT ;
    USE SIGNAL ;
    PORT
      LAYER M4 ;
        RECT  30.048 8.208 30.24 8.232 ;
    END
  END last[54]
  PIN last[55]
    DIRECTION OUTPUT ;
    USE SIGNAL ;
    PORT
      LAYER M4 ;
        RECT  30.048 8.304 30.24 8.328 ;
    END
  END last[55]
  PIN last[56]
    DIRECTION OUTPUT ;
    USE SIGNAL ;
    PORT
      LAYER M4 ;
        RECT  30.048 8.4 30.24 8.424 ;
    END
  END last[56]
  PIN last[57]
    DIRECTION OUTPUT ;
    USE SIGNAL ;
    PORT
      LAYER M4 ;
        RECT  30.048 8.496 30.24 8.52 ;
    END
  END last[57]
  PIN last[58]
    DIRECTION OUTPUT ;
    USE SIGNAL ;
    PORT
      LAYER M4 ;
        RECT  30.048 8.592 30.24 8.616 ;
    END
  END last[58]
  PIN last[59]
    DIRECTION OUTPUT ;
    USE SIGNAL ;
    PORT
      LAYER M4 ;
        RECT  30.048 8.688 30.24 8.712 ;
    END
  END last[59]
  PIN last[5]
    DIRECTION OUTPUT ;
    USE SIGNAL ;
    PORT
      LAYER M4 ;
        RECT  30.048 3.504 30.24 3.528 ;
    END
  END last[5]
  PIN last[60]
    DIRECTION OUTPUT ;
    USE SIGNAL ;
    PORT
      LAYER M4 ;
        RECT  30.048 8.784 30.24 8.808 ;
    END
  END last[60]
  PIN last[61]
    DIRECTION OUTPUT ;
    USE SIGNAL ;
    PORT
      LAYER M4 ;
        RECT  30.048 8.88 30.24 8.904 ;
    END
  END last[61]
  PIN last[62]
    DIRECTION OUTPUT ;
    USE SIGNAL ;
    PORT
      LAYER M4 ;
        RECT  30.048 8.976 30.24 9 ;
    END
  END last[62]
  PIN last[63]
    DIRECTION OUTPUT ;
    USE SIGNAL ;
    PORT
      LAYER M4 ;
        RECT  30.048 9.072 30.24 9.096 ;
    END
  END last[63]
  PIN last[64]
    DIRECTION OUTPUT ;
    USE SIGNAL ;
    PORT
      LAYER M4 ;
        RECT  30.048 9.168 30.24 9.192 ;
    END
  END last[64]
  PIN last[65]
    DIRECTION OUTPUT ;
    USE SIGNAL ;
    PORT
      LAYER M4 ;
        RECT  30.048 9.264 30.24 9.288 ;
    END
  END last[65]
  PIN last[66]
    DIRECTION OUTPUT ;
    USE SIGNAL ;
    PORT
      LAYER M4 ;
        RECT  30.048 9.36 30.24 9.384 ;
    END
  END last[66]
  PIN last[67]
    DIRECTION OUTPUT ;
    USE SIGNAL ;
    PORT
      LAYER M4 ;
        RECT  30.048 9.456 30.24 9.48 ;
    END
  END last[67]
  PIN last[68]
    DIRECTION OUTPUT ;
    USE SIGNAL ;
    PORT
      LAYER M4 ;
        RECT  30.048 9.552 30.24 9.576 ;
    END
  END last[68]
  PIN last[69]
    DIRECTION OUTPUT ;
    USE SIGNAL ;
    PORT
      LAYER M4 ;
        RECT  30.048 9.648 30.24 9.672 ;
    END
  END last[69]
  PIN last[6]
    DIRECTION OUTPUT ;
    USE SIGNAL ;
    PORT
      LAYER M4 ;
        RECT  30.048 3.6 30.24 3.624 ;
    END
  END last[6]
  PIN last[70]
    DIRECTION OUTPUT ;
    USE SIGNAL ;
    PORT
      LAYER M4 ;
        RECT  30.048 9.744 30.24 9.768 ;
    END
  END last[70]
  PIN last[71]
    DIRECTION OUTPUT ;
    USE SIGNAL ;
    PORT
      LAYER M4 ;
        RECT  30.048 9.84 30.24 9.864 ;
    END
  END last[71]
  PIN last[72]
    DIRECTION OUTPUT ;
    USE SIGNAL ;
    PORT
      LAYER M4 ;
        RECT  30.048 9.936 30.24 9.96 ;
    END
  END last[72]
  PIN last[73]
    DIRECTION OUTPUT ;
    USE SIGNAL ;
    PORT
      LAYER M4 ;
        RECT  30.048 10.032 30.24 10.056 ;
    END
  END last[73]
  PIN last[74]
    DIRECTION OUTPUT ;
    USE SIGNAL ;
    PORT
      LAYER M4 ;
        RECT  30.048 10.128 30.24 10.152 ;
    END
  END last[74]
  PIN last[75]
    DIRECTION OUTPUT ;
    USE SIGNAL ;
    PORT
      LAYER M4 ;
        RECT  30.048 10.224 30.24 10.248 ;
    END
  END last[75]
  PIN last[76]
    DIRECTION OUTPUT ;
    USE SIGNAL ;
    PORT
      LAYER M4 ;
        RECT  30.048 10.32 30.24 10.344 ;
    END
  END last[76]
  PIN last[77]
    DIRECTION OUTPUT ;
    USE SIGNAL ;
    PORT
      LAYER M4 ;
        RECT  30.048 10.416 30.24 10.44 ;
    END
  END last[77]
  PIN last[78]
    DIRECTION OUTPUT ;
    USE SIGNAL ;
    PORT
      LAYER M4 ;
        RECT  30.048 10.512 30.24 10.536 ;
    END
  END last[78]
  PIN last[79]
    DIRECTION OUTPUT ;
    USE SIGNAL ;
    PORT
      LAYER M4 ;
        RECT  30.048 10.608 30.24 10.632 ;
    END
  END last[79]
  PIN last[7]
    DIRECTION OUTPUT ;
    USE SIGNAL ;
    PORT
      LAYER M4 ;
        RECT  30.048 3.696 30.24 3.72 ;
    END
  END last[7]
  PIN last[80]
    DIRECTION OUTPUT ;
    USE SIGNAL ;
    PORT
      LAYER M4 ;
        RECT  30.048 10.704 30.24 10.728 ;
    END
  END last[80]
  PIN last[81]
    DIRECTION OUTPUT ;
    USE SIGNAL ;
    PORT
      LAYER M4 ;
        RECT  30.048 10.8 30.24 10.824 ;
    END
  END last[81]
  PIN last[82]
    DIRECTION OUTPUT ;
    USE SIGNAL ;
    PORT
      LAYER M4 ;
        RECT  30.048 10.896 30.24 10.92 ;
    END
  END last[82]
  PIN last[83]
    DIRECTION OUTPUT ;
    USE SIGNAL ;
    PORT
      LAYER M4 ;
        RECT  30.048 10.992 30.24 11.016 ;
    END
  END last[83]
  PIN last[84]
    DIRECTION OUTPUT ;
    USE SIGNAL ;
    PORT
      LAYER M4 ;
        RECT  30.048 11.088 30.24 11.112 ;
    END
  END last[84]
  PIN last[85]
    DIRECTION OUTPUT ;
    USE SIGNAL ;
    PORT
      LAYER M4 ;
        RECT  30.048 11.184 30.24 11.208 ;
    END
  END last[85]
  PIN last[86]
    DIRECTION OUTPUT ;
    USE SIGNAL ;
    PORT
      LAYER M4 ;
        RECT  30.048 11.28 30.24 11.304 ;
    END
  END last[86]
  PIN last[87]
    DIRECTION OUTPUT ;
    USE SIGNAL ;
    PORT
      LAYER M4 ;
        RECT  30.048 11.376 30.24 11.4 ;
    END
  END last[87]
  PIN last[88]
    DIRECTION OUTPUT ;
    USE SIGNAL ;
    PORT
      LAYER M4 ;
        RECT  30.048 11.472 30.24 11.496 ;
    END
  END last[88]
  PIN last[89]
    DIRECTION OUTPUT ;
    USE SIGNAL ;
    PORT
      LAYER M4 ;
        RECT  30.048 11.568 30.24 11.592 ;
    END
  END last[89]
  PIN last[8]
    DIRECTION OUTPUT ;
    USE SIGNAL ;
    PORT
      LAYER M4 ;
        RECT  30.048 3.792 30.24 3.816 ;
    END
  END last[8]
  PIN last[90]
    DIRECTION OUTPUT ;
    USE SIGNAL ;
    PORT
      LAYER M4 ;
        RECT  30.048 11.664 30.24 11.688 ;
    END
  END last[90]
  PIN last[91]
    DIRECTION OUTPUT ;
    USE SIGNAL ;
    PORT
      LAYER M4 ;
        RECT  30.048 11.76 30.24 11.784 ;
    END
  END last[91]
  PIN last[92]
    DIRECTION OUTPUT ;
    USE SIGNAL ;
    PORT
      LAYER M4 ;
        RECT  30.048 11.856 30.24 11.88 ;
    END
  END last[92]
  PIN last[93]
    DIRECTION OUTPUT ;
    USE SIGNAL ;
    PORT
      LAYER M4 ;
        RECT  30.048 11.952 30.24 11.976 ;
    END
  END last[93]
  PIN last[94]
    DIRECTION OUTPUT ;
    USE SIGNAL ;
    PORT
      LAYER M4 ;
        RECT  30.048 12.048 30.24 12.072 ;
    END
  END last[94]
  PIN last[95]
    DIRECTION OUTPUT ;
    USE SIGNAL ;
    PORT
      LAYER M4 ;
        RECT  30.048 12.144 30.24 12.168 ;
    END
  END last[95]
  PIN last[96]
    DIRECTION OUTPUT ;
    USE SIGNAL ;
    PORT
      LAYER M4 ;
        RECT  30.048 12.24 30.24 12.264 ;
    END
  END last[96]
  PIN last[97]
    DIRECTION OUTPUT ;
    USE SIGNAL ;
    PORT
      LAYER M4 ;
        RECT  30.048 12.336 30.24 12.36 ;
    END
  END last[97]
  PIN last[98]
    DIRECTION OUTPUT ;
    USE SIGNAL ;
    PORT
      LAYER M4 ;
        RECT  30.048 12.432 30.24 12.456 ;
    END
  END last[98]
  PIN last[99]
    DIRECTION OUTPUT ;
    USE SIGNAL ;
    PORT
      LAYER M4 ;
        RECT  30.048 12.528 30.24 12.552 ;
    END
  END last[99]
  PIN last[9]
    DIRECTION OUTPUT ;
    USE SIGNAL ;
    PORT
      LAYER M4 ;
        RECT  30.048 3.888 30.24 3.912 ;
    END
  END last[9]
  PIN rst_a
    DIRECTION INPUT ;
    USE SIGNAL ;
    PORT
      LAYER M5 ;
        RECT  1.488 30.048 1.512 30.24 ;
    END
  END rst_a
  PIN VDD
    DIRECTION INOUT ;
    USE POWER ;
    PORT
      LAYER M5 ;
        RECT  24.192 2.151 24.312 28.089 ;
        RECT  18.792 2.151 18.912 28.089 ;
        RECT  13.392 2.151 13.512 28.089 ;
        RECT  7.992 2.151 8.112 28.089 ;
        RECT  2.592 2.151 2.712 28.089 ;
    END
  END VDD
  PIN VSS
    DIRECTION INOUT ;
    USE GROUND ;
    PORT
      LAYER M5 ;
        RECT  24 2.137 24.12 28.103 ;
        RECT  18.6 2.137 18.72 28.103 ;
        RECT  13.2 2.137 13.32 28.103 ;
        RECT  7.8 2.137 7.92 28.103 ;
        RECT  2.4 2.137 2.52 28.103 ;
    END
  END VSS
  # OT_OBS_CLOSED layer=M5 d_um=1.536 added=27
  OBS
    LAYER RVTN ;
     RECT  2.16 2.16 28.08 2.295 ;
     RECT  2.16 2.565 28.08 2.835 ;
     RECT  2.16 3.105 28.08 3.375 ;
     RECT  2.16 3.645 28.08 3.915 ;
     RECT  2.16 4.185 28.08 4.455 ;
     RECT  2.16 4.725 28.08 4.995 ;
     RECT  2.16 5.265 28.08 5.535 ;
     RECT  2.16 5.805 28.08 6.075 ;
     RECT  2.16 6.345 28.08 6.615 ;
     RECT  2.16 6.885 28.08 7.155 ;
     RECT  2.16 7.425 28.08 7.695 ;
     RECT  2.16 7.965 28.08 8.235 ;
     RECT  2.16 8.505 28.08 8.775 ;
     RECT  2.16 9.045 28.08 9.315 ;
     RECT  2.16 9.585 28.08 9.855 ;
     RECT  2.16 10.125 28.08 10.395 ;
     RECT  2.16 10.665 28.08 10.935 ;
     RECT  2.16 11.205 28.08 11.475 ;
     RECT  2.16 11.745 28.08 12.015 ;
     RECT  2.16 12.285 28.08 12.555 ;
     RECT  2.16 12.825 28.08 13.095 ;
     RECT  2.16 13.365 28.08 13.635 ;
     RECT  2.16 13.905 28.08 14.175 ;
     RECT  2.16 14.445 28.08 14.715 ;
     RECT  2.16 14.985 28.08 15.255 ;
     RECT  2.16 15.525 28.08 15.795 ;
     RECT  2.16 16.065 28.08 16.335 ;
     RECT  2.16 16.605 28.08 16.875 ;
     RECT  2.16 17.145 28.08 17.415 ;
     RECT  2.16 17.685 28.08 17.955 ;
     RECT  2.16 18.225 28.08 18.495 ;
     RECT  2.16 18.765 28.08 19.035 ;
     RECT  2.16 19.305 28.08 19.575 ;
     RECT  2.16 19.845 28.08 20.115 ;
     RECT  2.16 20.385 28.08 20.655 ;
     RECT  2.16 20.925 28.08 21.195 ;
     RECT  2.16 21.465 28.08 21.735 ;
     RECT  2.16 22.005 28.08 22.275 ;
     RECT  2.16 22.545 28.08 22.815 ;
     RECT  2.16 23.085 28.08 23.355 ;
     RECT  2.16 23.625 28.08 23.895 ;
     RECT  2.16 24.165 28.08 24.435 ;
     RECT  2.16 24.705 28.08 24.975 ;
     RECT  2.16 25.245 28.08 25.515 ;
     RECT  2.16 25.785 28.08 26.055 ;
     RECT  2.16 26.325 28.08 26.595 ;
     RECT  2.16 26.865 28.08 27.135 ;
     RECT  2.16 27.405 28.08 27.675 ;
     RECT  2.16 27.945 28.08 28.08 ;
    LAYER RVTP ;
     RECT  2.16 2.295 28.08 2.565 ;
     RECT  2.16 2.835 28.08 3.105 ;
     RECT  2.16 3.375 28.08 3.645 ;
     RECT  2.16 3.915 28.08 4.185 ;
     RECT  2.16 4.455 28.08 4.725 ;
     RECT  2.16 4.995 28.08 5.265 ;
     RECT  2.16 5.535 28.08 5.805 ;
     RECT  2.16 6.075 28.08 6.345 ;
     RECT  2.16 6.615 28.08 6.885 ;
     RECT  2.16 7.155 28.08 7.425 ;
     RECT  2.16 7.695 28.08 7.965 ;
     RECT  2.16 8.235 28.08 8.505 ;
     RECT  2.16 8.775 28.08 9.045 ;
     RECT  2.16 9.315 28.08 9.585 ;
     RECT  2.16 9.855 28.08 10.125 ;
     RECT  2.16 10.395 28.08 10.665 ;
     RECT  2.16 10.935 28.08 11.205 ;
     RECT  2.16 11.475 28.08 11.745 ;
     RECT  2.16 12.015 28.08 12.285 ;
     RECT  2.16 12.555 28.08 12.825 ;
     RECT  2.16 13.095 28.08 13.365 ;
     RECT  2.16 13.635 28.08 13.905 ;
     RECT  2.16 14.175 28.08 14.445 ;
     RECT  2.16 14.715 28.08 14.985 ;
     RECT  2.16 15.255 28.08 15.525 ;
     RECT  2.16 15.795 28.08 16.065 ;
     RECT  2.16 16.335 28.08 16.605 ;
     RECT  2.16 16.875 28.08 17.145 ;
     RECT  2.16 17.415 28.08 17.685 ;
     RECT  2.16 17.955 28.08 18.225 ;
     RECT  2.16 18.495 28.08 18.765 ;
     RECT  2.16 19.035 28.08 19.305 ;
     RECT  2.16 19.575 28.08 19.845 ;
     RECT  2.16 20.115 28.08 20.385 ;
     RECT  2.16 20.655 28.08 20.925 ;
     RECT  2.16 21.195 28.08 21.465 ;
     RECT  2.16 21.735 28.08 22.005 ;
     RECT  2.16 22.275 28.08 22.545 ;
     RECT  2.16 22.815 28.08 23.085 ;
     RECT  2.16 23.355 28.08 23.625 ;
     RECT  2.16 23.895 28.08 24.165 ;
     RECT  2.16 24.435 28.08 24.705 ;
     RECT  2.16 24.975 28.08 25.245 ;
     RECT  2.16 25.515 28.08 25.785 ;
     RECT  2.16 26.055 28.08 26.325 ;
     RECT  2.16 26.595 28.08 26.865 ;
     RECT  2.16 27.135 28.08 27.405 ;
     RECT  2.16 27.675 28.08 27.945 ;
    LAYER M1 ;
     RECT  2.16 2.151 28.08 28.089 ;
    LAYER M2 ;
     RECT  0.031 2.646 0.211 2.934 ;
     RECT  0.211 2.61 0.239 2.934 ;
     RECT  0.239 2.61 0.283 2.862 ;
     RECT  0.247 6.012 0.283 6.03 ;
     RECT  0.211 9.09 0.319 9.27 ;
     RECT  0.283 2.502 0.383 2.862 ;
     RECT  0.211 14.148 0.419 14.166 ;
     RECT  1.723 16.002 2.047 16.02 ;
     RECT  0.383 2.502 2.16 2.826 ;
     RECT  0.283 6.012 2.16 6.372 ;
     RECT  0.211 7.398 2.16 7.416 ;
     RECT  0.319 8.514 2.16 9.27 ;
     RECT  0.211 12.492 2.16 12.51 ;
     RECT  2.047 16.002 2.16 16.092 ;
     RECT  1.399 17.892 2.16 17.91 ;
     RECT  13.531 29.034 13.631 29.052 ;
     RECT  2.16 2.151 23.863 28.089 ;
     RECT  23.863 2.034 26.195 28.089 ;
     RECT  26.195 2.106 26.375 28.089 ;
     RECT  26.375 2.151 28.08 28.089 ;
     RECT  28.08 2.574 28.535 19.494 ;
     RECT  28.535 2.646 28.679 19.494 ;
     RECT  28.679 18.936 28.787 19.494 ;
     RECT  28.787 18.936 28.859 18.954 ;
     RECT  28.679 2.646 29.111 18.144 ;
     RECT  29.111 5.616 29.147 8.334 ;
     RECT  29.111 9.252 29.147 18.144 ;
     RECT  29.147 15.264 29.183 18.144 ;
     RECT  29.147 10.476 29.255 14.004 ;
     RECT  29.183 15.534 29.363 18.144 ;
     RECT  29.363 15.534 29.435 17.334 ;
     RECT  29.147 8.136 29.651 8.154 ;
     RECT  29.147 9.252 29.651 9.576 ;
     RECT  29.255 10.476 29.651 13.554 ;
     RECT  29.363 18.126 29.651 18.144 ;
     RECT  29.111 2.646 29.687 4.518 ;
     RECT  29.147 5.616 29.687 7.218 ;
     RECT  29.651 9.558 29.687 9.576 ;
     RECT  29.651 10.476 29.687 10.764 ;
     RECT  29.651 11.52 29.687 12.888 ;
     RECT  29.435 15.534 29.687 17.1 ;
     RECT  29.687 4.266 29.723 4.446 ;
     RECT  29.687 6.084 29.723 6.219 ;
     RECT  29.687 6.966 29.723 7.218 ;
     RECT  29.687 10.746 29.723 10.764 ;
     RECT  29.687 12.366 29.723 12.852 ;
     RECT  29.723 4.266 29.759 4.374 ;
     RECT  29.723 6.201 29.759 6.219 ;
     RECT  29.723 7.2 29.759 7.218 ;
     RECT  29.723 12.834 29.759 12.852 ;
     RECT  29.687 2.646 29.795 3.402 ;
     RECT  29.687 16.236 29.903 17.1 ;
     RECT  29.903 17.082 29.975 17.1 ;
     RECT  29.795 2.646 30.011 2.664 ;
     RECT  29.903 16.236 30.011 16.254 ;
     RECT  29.759 4.266 30.083 4.284 ;
    LAYER M3 ;
     RECT  26.172 2.029 26.19 2.101 ;
     RECT  23.868 2.029 23.886 2.143 ;
     RECT  2.415 2.143 2.505 2.191 ;
     RECT  25.02 2.101 25.038 2.191 ;
     RECT  26.172 2.101 26.37 2.191 ;
     RECT  24.948 2.191 26.37 2.227 ;
     RECT  2.415 2.191 2.97 2.263 ;
     RECT  23.868 2.143 24.105 2.263 ;
     RECT  24.948 2.227 26.73 2.263 ;
     RECT  27.54 2.191 27.558 2.263 ;
     RECT  22.248 2.263 22.266 2.299 ;
     RECT  23.148 2.263 24.105 2.299 ;
     RECT  2.415 2.263 3.294 2.371 ;
     RECT  4.032 2.191 4.05 2.371 ;
     RECT  22.248 2.299 24.105 2.371 ;
     RECT  24.948 2.263 27.99 2.371 ;
     RECT  7.815 2.143 7.905 2.413 ;
     RECT  13.215 2.143 13.305 2.413 ;
     RECT  18.615 2.143 18.705 2.413 ;
     RECT  4.824 2.371 4.842 2.461 ;
     RECT  6.192 2.371 6.21 2.489 ;
     RECT  9.144 2.191 9.162 2.497 ;
     RECT  2.415 2.371 4.05 2.533 ;
     RECT  18.615 2.413 18.897 2.533 ;
     RECT  10.332 2.497 10.35 2.569 ;
     RECT  22.248 2.371 27.99 2.569 ;
     RECT  0.288 2.497 0.306 2.605 ;
     RECT  4.824 2.461 5.13 2.605 ;
     RECT  21.096 2.569 21.114 2.605 ;
     RECT  0.216 2.605 0.306 2.641 ;
     RECT  2.304 2.533 4.05 2.641 ;
     RECT  4.824 2.605 5.202 2.641 ;
     RECT  10.296 2.569 10.35 2.641 ;
     RECT  11.16 2.605 11.178 2.641 ;
     RECT  21.06 2.605 21.114 2.641 ;
     RECT  7.815 2.413 8.097 2.731 ;
     RECT  18.615 2.533 19.206 2.731 ;
     RECT  19.944 2.641 21.114 2.731 ;
     RECT  22.248 2.569 28.53 2.731 ;
     RECT  29.988 2.641 30.006 2.731 ;
     RECT  13.215 2.413 13.497 2.767 ;
     RECT  14.688 2.227 14.706 2.767 ;
     RECT  9.108 2.497 9.162 2.795 ;
     RECT  0.036 2.641 0.306 2.803 ;
     RECT  0.036 2.803 0.342 2.839 ;
     RECT  18.615 2.731 21.114 2.875 ;
     RECT  21.96 2.731 29.106 2.875 ;
     RECT  6.228 2.569 6.246 2.911 ;
     RECT  10.26 2.641 11.178 2.911 ;
     RECT  13.215 2.767 14.706 2.911 ;
     RECT  15.84 2.875 15.858 2.911 ;
     RECT  17.1 2.731 17.118 2.911 ;
     RECT  0.036 2.839 0.378 2.939 ;
     RECT  17.1 2.911 17.298 3.001 ;
     RECT  13.215 2.911 15.858 3.101 ;
     RECT  6.228 2.911 6.426 3.109 ;
     RECT  14.22 3.101 15.858 3.109 ;
     RECT  9.936 2.911 11.178 3.181 ;
     RECT  17.1 3.001 17.874 3.181 ;
     RECT  2.304 2.641 5.202 3.211 ;
     RECT  6.228 3.109 7.074 3.271 ;
     RECT  7.815 2.731 8.154 3.271 ;
     RECT  14.22 3.109 15.966 3.271 ;
     RECT  16.812 3.181 17.874 3.271 ;
     RECT  9.108 2.795 9.126 3.299 ;
     RECT  9.936 3.181 11.25 3.335 ;
     RECT  7.815 3.271 8.19 3.371 ;
     RECT  2.268 3.211 5.202 3.379 ;
     RECT  5.976 3.271 7.074 3.379 ;
     RECT  18.615 2.875 29.106 3.379 ;
     RECT  29.988 2.731 30.078 3.379 ;
     RECT  14.22 3.271 17.874 3.451 ;
     RECT  18.615 3.379 30.078 3.451 ;
     RECT  0.216 2.939 0.378 3.533 ;
     RECT  14.22 3.451 30.078 3.569 ;
     RECT  2.268 3.379 7.074 3.577 ;
     RECT  7.815 3.371 8.097 3.577 ;
     RECT  0.216 3.533 0.342 3.821 ;
     RECT  14.22 3.569 15.21 3.839 ;
     RECT  14.508 3.839 15.066 3.875 ;
     RECT  10.656 3.335 11.25 3.883 ;
     RECT  15.948 3.569 30.078 3.911 ;
     RECT  2.268 3.577 8.097 3.955 ;
     RECT  17.1 3.911 30.078 4.019 ;
     RECT  15.948 3.911 16.218 4.109 ;
     RECT  2.232 3.955 8.097 4.219 ;
     RECT  10.656 3.883 11.826 4.261 ;
     RECT  19.908 4.019 30.078 4.289 ;
     RECT  19.908 4.289 30.006 4.301 ;
     RECT  10.584 4.261 11.826 4.379 ;
     RECT  2.196 4.219 8.097 4.397 ;
     RECT  0.216 3.821 0.27 4.555 ;
     RECT  15.048 3.875 15.066 4.657 ;
     RECT  0.216 4.555 0.414 4.685 ;
     RECT  19.908 4.301 28.746 4.721 ;
     RECT  14.868 4.657 15.066 4.729 ;
     RECT  19.908 4.721 28.062 4.757 ;
     RECT  16.02 4.109 16.218 4.801 ;
     RECT  17.1 4.019 18.99 4.801 ;
     RECT  19.908 4.757 27.882 4.801 ;
     RECT  16.02 4.801 27.882 4.829 ;
     RECT  10.8 4.379 11.826 4.891 ;
     RECT  10.8 4.891 12.078 4.919 ;
     RECT  2.232 4.397 8.097 4.927 ;
     RECT  8.892 4.765 8.91 4.927 ;
     RECT  29.664 4.301 30.006 5.035 ;
     RECT  14.22 4.729 15.246 5.071 ;
     RECT  2.232 4.927 8.91 5.099 ;
     RECT  11.484 4.919 12.078 5.099 ;
     RECT  0.216 4.685 0.342 5.117 ;
     RECT  2.268 5.099 8.91 5.189 ;
     RECT  16.56 4.829 27.882 5.189 ;
     RECT  9.684 3.649 9.702 5.225 ;
     RECT  0.216 5.117 0.234 5.261 ;
     RECT  13.215 3.101 13.497 5.269 ;
     RECT  14.22 5.071 15.534 5.269 ;
     RECT  11.484 5.099 11.574 5.369 ;
     RECT  2.268 5.189 8.154 5.453 ;
     RECT  11.484 5.369 11.538 5.495 ;
     RECT  16.56 5.189 19.422 5.611 ;
     RECT  13.215 5.269 15.534 5.701 ;
     RECT  29.088 5.035 30.006 5.741 ;
     RECT  10.764 5.701 11.358 5.809 ;
     RECT  16.488 5.611 19.422 5.809 ;
     RECT  2.304 5.453 8.154 5.971 ;
     RECT  9.036 5.233 9.126 5.971 ;
     RECT  13.215 5.701 15.642 5.971 ;
     RECT  16.452 5.809 19.422 5.971 ;
     RECT  20.412 5.189 27.882 5.995 ;
     RECT  13.215 5.971 19.458 6.043 ;
     RECT  20.412 5.995 27.954 6.043 ;
     RECT  0.252 6.007 0.27 6.079 ;
     RECT  2.304 5.971 9.126 6.115 ;
     RECT  10.224 5.809 11.358 6.115 ;
     RECT  20.412 6.043 27.99 6.115 ;
     RECT  2.304 6.115 11.358 6.143 ;
     RECT  29.088 5.741 29.754 6.179 ;
     RECT  20.34 6.115 28.134 6.224 ;
     RECT  13.215 6.043 19.53 6.269 ;
     RECT  9.432 6.143 11.358 6.305 ;
     RECT  14.4 6.269 19.53 6.385 ;
     RECT  10.116 6.305 11.358 6.539 ;
     RECT  2.304 6.143 8.586 6.575 ;
     RECT  14.4 6.385 19.566 6.691 ;
     RECT  20.34 6.224 28.026 6.691 ;
     RECT  0.252 6.079 0.558 6.797 ;
     RECT  10.116 6.539 11.322 6.845 ;
     RECT  14.4 6.691 28.026 6.845 ;
     RECT  14.4 6.845 27.954 6.953 ;
     RECT  2.304 6.575 8.406 7.051 ;
     RECT  10.152 6.845 11.322 7.079 ;
     RECT  10.224 7.079 11.322 7.115 ;
     RECT  29.124 6.179 29.754 7.147 ;
     RECT  0.252 6.797 0.306 7.181 ;
     RECT  2.268 7.051 8.406 7.187 ;
     RECT  14.4 6.953 20.106 7.321 ;
     RECT  10.764 7.115 11.322 7.465 ;
     RECT  12.06 7.429 12.078 7.465 ;
     RECT  29.088 7.147 29.754 7.469 ;
     RECT  2.304 7.187 8.406 7.591 ;
     RECT  10.764 7.465 12.294 7.655 ;
     RECT  0.216 7.393 0.234 7.661 ;
     RECT  20.916 6.953 27.954 7.661 ;
     RECT  10.764 7.655 12.042 7.691 ;
     RECT  29.088 7.469 29.646 7.723 ;
     RECT  13.215 6.269 13.497 7.771 ;
     RECT  14.328 7.321 20.106 7.771 ;
     RECT  20.916 7.661 27.738 7.771 ;
     RECT  11.664 7.691 12.042 7.799 ;
     RECT  11.664 7.799 12.006 7.889 ;
     RECT  12.78 7.771 27.738 7.889 ;
     RECT  11.736 7.889 11.934 7.961 ;
     RECT  28.512 7.723 29.646 8.159 ;
     RECT  12.78 7.889 27.666 8.195 ;
     RECT  10.764 7.691 10.854 8.311 ;
     RECT  12.78 8.195 15.426 8.339 ;
     RECT  2.304 7.591 8.658 8.401 ;
     RECT  9.684 8.311 10.854 8.401 ;
     RECT  2.304 8.401 10.854 8.429 ;
     RECT  9 8.429 10.854 8.501 ;
     RECT  10.728 8.501 10.854 8.509 ;
     RECT  16.524 8.195 27.666 8.525 ;
     RECT  0.324 8.509 0.342 8.587 ;
     RECT  28.512 8.159 29.178 8.683 ;
     RECT  9 8.501 9.702 8.735 ;
     RECT  10.728 8.509 10.926 8.735 ;
     RECT  21.096 8.525 27.666 8.843 ;
     RECT  10.764 8.735 10.926 8.851 ;
     RECT  11.736 7.961 11.754 8.851 ;
     RECT  16.524 8.525 20.214 8.879 ;
     RECT  28.476 8.683 29.178 8.923 ;
     RECT  0.252 8.587 0.342 8.941 ;
     RECT  10.764 8.851 11.97 8.941 ;
     RECT  12.78 8.339 13.497 8.941 ;
     RECT  16.524 8.879 20.034 8.977 ;
     RECT  14.472 8.339 15.426 9.049 ;
     RECT  0.252 8.941 0.558 9.085 ;
     RECT  22.032 8.843 27.666 9.163 ;
     RECT  28.476 8.923 29.286 9.163 ;
     RECT  14.472 9.049 15.462 9.247 ;
     RECT  22.032 9.163 29.286 9.247 ;
     RECT  14.292 9.247 15.462 9.391 ;
     RECT  16.452 8.977 20.034 9.391 ;
     RECT  21.096 8.843 21.258 9.391 ;
     RECT  14.292 9.391 20.034 9.419 ;
     RECT  22.032 9.247 29.646 9.545 ;
     RECT  22.248 9.545 29.646 9.553 ;
     RECT  20.952 9.391 21.258 9.581 ;
     RECT  2.304 8.429 8.226 9.589 ;
     RECT  20.952 9.581 21.186 9.589 ;
     RECT  2.304 9.589 8.262 9.661 ;
     RECT  9 8.735 9.018 9.661 ;
     RECT  0.216 9.085 0.558 9.773 ;
     RECT  2.304 9.661 9.018 9.823 ;
     RECT  14.328 9.419 20.034 9.851 ;
     RECT  10.764 8.941 13.497 9.923 ;
     RECT  10.908 9.923 13.497 9.959 ;
     RECT  0.54 9.773 0.558 9.965 ;
     RECT  15.624 9.851 20.034 10.021 ;
     RECT  20.808 9.589 21.186 10.021 ;
     RECT  2.304 9.823 9.162 10.057 ;
     RECT  2.304 10.057 9.666 10.075 ;
     RECT  11.196 9.959 13.497 10.085 ;
     RECT  12.78 10.085 13.497 10.229 ;
     RECT  22.248 9.553 29.682 10.315 ;
     RECT  15.624 10.021 21.186 10.327 ;
     RECT  22.248 10.315 29.718 10.327 ;
     RECT  2.304 10.075 9.702 10.435 ;
     RECT  15.624 10.327 29.718 10.697 ;
     RECT  2.304 10.435 10.026 10.741 ;
     RECT  11.196 10.085 12.006 10.741 ;
     RECT  14.328 9.851 14.886 10.831 ;
     RECT  15.624 10.697 19.278 10.831 ;
     RECT  2.304 10.741 12.006 10.895 ;
     RECT  14.328 10.831 19.278 10.903 ;
     RECT  14.22 10.903 19.278 10.931 ;
     RECT  10.728 10.895 12.006 10.975 ;
     RECT  14.22 10.931 15.462 11.129 ;
     RECT  14.364 11.129 15.462 11.237 ;
     RECT  0.252 11.131 0.27 11.309 ;
     RECT  2.304 10.895 9.882 11.371 ;
     RECT  13.215 10.229 13.497 11.371 ;
     RECT  2.268 11.371 9.882 11.435 ;
     RECT  10.728 10.975 12.078 11.551 ;
     RECT  16.272 10.931 19.278 11.551 ;
     RECT  20.052 10.697 29.718 11.551 ;
     RECT  16.272 11.551 29.718 11.785 ;
     RECT  2.304 11.435 9.882 11.821 ;
     RECT  10.728 11.551 12.15 11.821 ;
     RECT  16.2 11.785 29.718 11.939 ;
     RECT  16.2 11.939 20.718 11.975 ;
     RECT  2.304 11.821 12.15 12.019 ;
     RECT  13.104 11.371 13.497 12.055 ;
     RECT  14.436 11.237 15.462 12.055 ;
     RECT  13.104 12.055 15.462 12.091 ;
     RECT  16.2 11.975 20.214 12.091 ;
     RECT  13.104 12.091 20.214 12.119 ;
     RECT  21.456 11.939 29.718 12.139 ;
     RECT  2.304 12.019 12.366 12.326 ;
     RECT  2.304 12.326 12.33 12.427 ;
     RECT  2.268 12.427 12.33 12.479 ;
     RECT  13.215 12.119 20.214 12.515 ;
     RECT  0.216 12.487 0.234 12.557 ;
     RECT  21.456 12.139 29.754 12.793 ;
     RECT  21.348 12.793 29.754 12.857 ;
     RECT  21.348 12.857 29.682 12.865 ;
     RECT  21.276 12.865 29.682 12.901 ;
     RECT  20.988 12.901 29.682 12.941 ;
     RECT  13.215 12.515 13.698 12.991 ;
     RECT  14.472 12.515 19.386 13.019 ;
     RECT  0.252 12.619 0.27 13.037 ;
     RECT  13.104 12.991 13.698 13.085 ;
     RECT  13.215 13.085 13.698 13.091 ;
     RECT  0.396 13.099 0.414 13.229 ;
     RECT  14.472 13.019 15.426 13.289 ;
     RECT  20.988 12.941 29.646 13.289 ;
     RECT  21.96 13.289 29.646 13.325 ;
     RECT  20.196 12.515 20.214 13.369 ;
     RECT  20.988 13.289 21.222 13.369 ;
     RECT  14.652 13.289 15.426 13.433 ;
     RECT  16.272 13.019 19.386 13.603 ;
     RECT  20.16 13.369 21.222 13.603 ;
     RECT  2.268 12.479 12.15 13.711 ;
     RECT  2.268 13.711 12.366 13.771 ;
     RECT  22.248 13.325 29.646 13.771 ;
     RECT  2.232 13.771 12.366 13.829 ;
     RECT  13.215 13.091 13.497 13.837 ;
     RECT  16.272 13.603 21.222 13.865 ;
     RECT  22.248 13.771 30.006 13.937 ;
     RECT  16.992 13.865 21.222 13.973 ;
     RECT  16.992 13.973 20.07 14.009 ;
     RECT  2.232 13.829 11.97 14.059 ;
     RECT  0.288 14.059 0.414 14.143 ;
     RECT  0.216 14.143 0.414 14.189 ;
     RECT  20.952 13.973 21.222 14.251 ;
     RECT  13.215 13.837 13.662 14.449 ;
     RECT  0.252 14.189 0.414 14.669 ;
     RECT  12.744 14.449 13.662 14.683 ;
     RECT  14.652 13.433 14.994 14.683 ;
     RECT  15.984 14.521 16.002 14.791 ;
     RECT  17.064 14.009 20.07 14.791 ;
     RECT  20.952 14.251 21.33 14.791 ;
     RECT  0.252 14.669 0.27 14.813 ;
     RECT  1.404 14.251 1.422 14.827 ;
     RECT  2.196 14.059 11.97 14.827 ;
     RECT  22.356 13.937 30.006 14.971 ;
     RECT  15.984 14.791 21.474 15.061 ;
     RECT  22.212 14.971 30.006 15.061 ;
     RECT  1.404 14.827 11.97 15.187 ;
     RECT  12.744 14.683 14.994 15.187 ;
     RECT  15.984 15.061 30.006 15.287 ;
     RECT  1.404 15.187 14.994 15.331 ;
     RECT  16.668 15.287 30.006 15.359 ;
     RECT  16.668 15.359 20.034 15.521 ;
     RECT  17.208 15.521 20.034 15.719 ;
     RECT  22.464 15.359 30.006 15.719 ;
     RECT  17.208 15.719 17.838 15.863 ;
     RECT  17.208 15.863 17.802 15.989 ;
     RECT  21.096 15.359 21.726 15.989 ;
     RECT  1.404 15.331 15.498 16.097 ;
     RECT  18.615 15.719 20.034 16.141 ;
     RECT  22.608 15.719 30.006 16.259 ;
     RECT  18.615 16.141 20.106 16.375 ;
     RECT  2.34 16.097 15.498 16.411 ;
     RECT  17.208 15.989 17.226 16.529 ;
     RECT  22.608 16.259 22.842 16.529 ;
     RECT  23.616 16.259 29.97 16.529 ;
     RECT  2.34 16.411 16.002 16.709 ;
     RECT  18.615 16.375 20.25 16.709 ;
     RECT  21.132 15.989 21.474 16.799 ;
     RECT  18.615 16.709 19.926 17.069 ;
     RECT  23.832 16.529 29.97 17.105 ;
     RECT  18.615 17.069 19.71 17.249 ;
     RECT  2.34 16.709 15.39 17.339 ;
     RECT  20.88 16.915 20.898 17.609 ;
     RECT  1.404 16.097 1.422 17.915 ;
     RECT  23.832 17.105 29.646 17.987 ;
     RECT  29.628 17.987 29.646 18.149 ;
     RECT  18.615 17.249 19.566 18.419 ;
     RECT  2.34 17.339 14.634 18.571 ;
     RECT  15.372 17.339 15.39 18.571 ;
     RECT  23.832 17.987 28.854 18.599 ;
     RECT  2.34 18.571 15.39 18.689 ;
     RECT  25.776 18.599 28.854 18.689 ;
     RECT  25.776 18.689 27.99 18.761 ;
     RECT  23.832 18.599 25.038 18.959 ;
     RECT  28.764 18.689 28.854 18.959 ;
     RECT  2.415 18.689 15.39 19.201 ;
     RECT  25.776 18.761 27.738 19.229 ;
     RECT  24.015 18.959 25.038 19.499 ;
     RECT  25.776 19.229 25.794 19.499 ;
     RECT  26.82 19.229 26.838 19.499 ;
     RECT  28.764 18.959 28.782 19.499 ;
     RECT  27.72 19.229 27.738 19.535 ;
     RECT  24.015 19.499 24.858 19.679 ;
     RECT  2.415 19.201 15.894 20.461 ;
     RECT  2.415 20.461 16.038 21.299 ;
     RECT  2.415 21.299 16.002 23.827 ;
     RECT  2.415 23.827 16.146 25.321 ;
     RECT  2.415 25.321 16.182 25.591 ;
     RECT  2.34 25.591 16.182 25.861 ;
     RECT  2.34 25.861 16.506 26.401 ;
     RECT  2.34 26.401 16.578 27.095 ;
     RECT  2.376 27.095 16.578 27.329 ;
     RECT  2.415 27.329 16.578 27.715 ;
     RECT  18.615 18.419 18.897 27.827 ;
     RECT  24.015 19.679 24.297 27.827 ;
     RECT  2.415 27.715 16.794 27.869 ;
     RECT  2.415 27.869 16.686 27.905 ;
     RECT  2.415 27.905 15.39 28.013 ;
     RECT  4.896 28.013 15.246 28.061 ;
     RECT  2.415 28.013 3.978 28.097 ;
     RECT  18.615 27.827 18.705 28.097 ;
     RECT  24.015 27.827 24.105 28.097 ;
     RECT  6.516 28.061 15.246 28.445 ;
     RECT  6.516 28.445 13.77 28.493 ;
     RECT  14.508 28.445 15.174 28.493 ;
     RECT  4.896 28.061 5.67 28.541 ;
     RECT  10.008 28.493 13.626 29.057 ;
     RECT  3.024 28.097 3.978 29.117 ;
     RECT  4.896 28.541 5.634 29.117 ;
     RECT  6.516 28.493 8.658 29.117 ;
     RECT  10.008 29.057 13.554 29.117 ;
     RECT  14.508 28.493 14.526 29.117 ;
     RECT  6.552 29.117 8.37 29.165 ;
     RECT  11.88 29.117 12.402 29.165 ;
     RECT  3.024 29.117 3.798 29.693 ;
     RECT  5.22 29.117 5.634 29.693 ;
     RECT  6.552 29.165 6.57 29.693 ;
     RECT  7.668 29.165 8.37 29.693 ;
     RECT  10.008 29.117 10.026 29.693 ;
     RECT  10.908 29.117 10.926 29.693 ;
     RECT  12.276 29.165 12.402 29.693 ;
     RECT  13.176 29.117 13.194 29.693 ;
     RECT  3.78 29.693 3.798 29.741 ;
     RECT  7.668 29.693 7.794 29.741 ;
     RECT  12.384 29.693 12.402 29.741 ;
     RECT  7.776 29.741 7.794 29.789 ;
     RECT  11.304 29.995 11.322 30.125 ;
    LAYER M4 ;
     RECT  0.156 3.024 2.293 15.24 ;
     RECT  2.293 2.496 2.329 15.24 ;
     RECT  2.329 2.496 2.408 15.576 ;
     RECT  2.365 17.472 2.408 17.496 ;
     RECT  2.293 21.696 2.408 21.72 ;
     RECT  2.408 2.148 2.512 28.092 ;
     RECT  2.512 2.4 2.704 28.092 ;
     RECT  2.704 21.12 2.765 21.72 ;
     RECT  2.704 14.64 2.801 15.24 ;
     RECT  2.704 23.568 2.819 23.592 ;
     RECT  2.704 2.4 2.873 2.424 ;
     RECT  2.704 3.408 2.873 13.08 ;
     RECT  2.801 14.64 2.873 14.664 ;
     RECT  2.873 8.016 2.909 8.52 ;
     RECT  2.704 27.936 3.068 28.092 ;
     RECT  2.873 6.24 3.125 6.696 ;
     RECT  3.068 27.936 3.229 28.536 ;
     RECT  2.972 29.664 3.229 29.688 ;
     RECT  2.765 21.12 3.347 21.144 ;
     RECT  3.229 27.936 3.736 29.688 ;
     RECT  2.873 3.408 3.769 5.16 ;
     RECT  3.736 27.936 3.827 29.736 ;
     RECT  3.769 2.496 3.877 5.16 ;
     RECT  3.827 27.936 3.917 29.112 ;
     RECT  2.873 9.504 3.949 13.08 ;
     RECT  3.877 26.688 4.069 26.712 ;
     RECT  4.021 20.256 4.309 20.28 ;
     RECT  3.125 6.24 4.345 6.552 ;
     RECT  3.877 2.496 4.385 5.208 ;
     RECT  4.345 6.24 4.489 6.696 ;
     RECT  3.949 9.12 4.489 13.08 ;
     RECT  3.841 14.784 4.489 14.808 ;
     RECT  4.261 25.056 4.565 25.08 ;
     RECT  4.489 9.072 4.597 13.08 ;
     RECT  4.489 14.112 4.597 14.808 ;
     RECT  4.561 22.8 4.633 22.824 ;
     RECT  4.069 26.688 4.645 26.808 ;
     RECT  3.917 27.936 4.645 28.008 ;
     RECT  4.597 9.072 4.705 14.808 ;
     RECT  4.633 22.8 4.777 23.016 ;
     RECT  2.704 16.512 4.813 18.696 ;
     RECT  2.909 8.016 4.849 8.04 ;
     RECT  4.645 26.688 4.849 28.008 ;
     RECT  4.705 9.072 4.885 15 ;
     RECT  4.813 16.416 4.885 18.696 ;
     RECT  3.917 29.088 4.925 29.112 ;
     RECT  4.309 20.256 4.933 20.568 ;
     RECT  3.913 21.648 4.933 21.672 ;
     RECT  4.385 2.496 4.961 3.432 ;
     RECT  4.933 20.256 4.979 21.672 ;
     RECT  4.385 4.512 5.029 5.208 ;
     RECT  4.489 6.24 5.029 6.84 ;
     RECT  4.849 26.4 5.029 28.008 ;
     RECT  5.029 26.4 5.077 28.056 ;
     RECT  4.849 7.872 5.101 8.04 ;
     RECT  4.885 9.072 5.101 18.696 ;
     RECT  4.777 22.8 5.123 23.4 ;
     RECT  5.029 4.512 5.18 6.84 ;
     RECT  5.101 7.872 5.18 18.696 ;
     RECT  5.077 26.208 5.213 28.056 ;
     RECT  4.961 3.408 5.267 3.432 ;
     RECT  5.18 4.512 5.267 18.696 ;
     RECT  4.979 20.544 5.317 21.672 ;
     RECT  5.213 26.736 5.317 28.056 ;
     RECT  5.267 4.512 5.363 6.84 ;
     RECT  5.363 4.512 5.393 5.16 ;
     RECT  5.221 25.104 5.429 25.128 ;
     RECT  5.317 26.736 5.5 28.584 ;
     RECT  5.5 26.736 5.681 28.536 ;
     RECT  5.267 7.872 5.749 18.696 ;
     RECT  5.749 7.872 6.035 19.416 ;
     RECT  5.363 6.24 6.041 6.84 ;
     RECT  5.123 23.376 6.073 23.4 ;
     RECT  5.681 26.736 6.076 28.056 ;
     RECT  6.073 23.376 6.157 23.928 ;
     RECT  5.393 4.896 6.179 5.16 ;
     RECT  6.076 27.936 6.268 28.056 ;
     RECT  5.701 25.056 6.289 25.08 ;
     RECT  6.179 5.136 6.293 5.16 ;
     RECT  6.035 7.872 6.325 13.224 ;
     RECT  5.317 20.544 6.325 22.248 ;
     RECT  6.157 23.376 6.325 23.4 ;
     RECT  6.035 14.256 6.365 19.416 ;
     RECT  6.289 24.432 6.433 25.08 ;
     RECT  6.076 26.736 6.433 26.856 ;
     RECT  5.125 29.664 6.469 29.688 ;
     RECT  6.365 14.352 6.517 19.416 ;
     RECT  6.325 20.544 6.517 23.4 ;
     RECT  6.433 24.432 6.545 26.856 ;
     RECT  6.469 29.088 6.581 29.688 ;
     RECT  6.517 14.352 6.689 23.4 ;
     RECT  6.041 6.24 6.793 6.312 ;
     RECT  6.793 6 7.009 6.312 ;
     RECT  6.325 7.344 7.009 13.224 ;
     RECT  6.545 24.528 7.153 26.856 ;
     RECT  6.268 27.936 7.153 27.96 ;
     RECT  6.581 29.088 7.324 29.16 ;
     RECT  7.153 24.528 7.621 27.96 ;
     RECT  7.621 29.664 7.657 29.688 ;
     RECT  7.657 29.664 7.762 29.736 ;
     RECT  7.009 6 7.808 13.32 ;
     RECT  6.689 14.352 7.808 23.112 ;
     RECT  7.621 24.528 7.808 28.248 ;
     RECT  7.762 29.664 7.859 29.784 ;
     RECT  7.808 2.148 7.912 28.248 ;
     RECT  7.912 2.418 8.104 28.248 ;
     RECT  8.104 14.448 8.165 14.76 ;
     RECT  8.104 10.08 8.201 13.176 ;
     RECT  8.104 25.44 8.243 28.248 ;
     RECT  8.165 14.448 8.339 14.712 ;
     RECT  7.859 29.664 8.381 29.688 ;
     RECT  8.104 16.512 8.417 23.928 ;
     RECT  8.201 10.08 8.489 13.08 ;
     RECT  8.243 25.488 8.579 28.248 ;
     RECT  8.579 25.68 8.581 28.248 ;
     RECT  8.581 25.68 8.597 29.112 ;
     RECT  8.597 27.936 8.669 29.112 ;
     RECT  8.417 20.592 8.675 23.928 ;
     RECT  8.675 22.752 8.813 23.928 ;
     RECT  8.597 25.68 8.893 26.808 ;
     RECT  8.675 20.592 8.957 21.672 ;
     RECT  8.893 26.208 8.963 26.808 ;
     RECT  8.813 23.088 9.173 23.928 ;
     RECT  8.963 26.208 9.245 26.232 ;
     RECT  8.339 14.64 9.313 14.712 ;
     RECT  9.173 23.088 9.317 23.4 ;
     RECT  8.489 11.136 9.425 13.08 ;
     RECT  8.417 16.512 9.493 19.608 ;
     RECT  9.425 11.664 9.605 13.08 ;
     RECT  9.521 24.48 9.605 24.504 ;
     RECT  9.317 23.088 9.649 23.352 ;
     RECT  9.493 16.512 9.683 20.136 ;
     RECT  8.489 10.08 9.713 10.104 ;
     RECT  8.669 27.936 9.733 29.064 ;
     RECT  9.733 27.936 9.829 29.688 ;
     RECT  8.957 21.12 10.109 21.672 ;
     RECT  9.853 25.104 10.181 25.128 ;
     RECT  9.925 22.656 10.505 22.728 ;
     RECT  9.313 14.448 10.681 14.712 ;
     RECT  9.829 27.312 10.78 29.688 ;
     RECT  10.681 14.352 10.825 14.712 ;
     RECT  9.683 16.512 10.825 17.208 ;
     RECT  10.825 14.208 10.933 14.712 ;
     RECT  10.933 14.208 11.045 14.808 ;
     RECT  10.78 27.936 11.189 29.688 ;
     RECT  10.109 21.168 11.257 21.672 ;
     RECT  11.189 29.088 11.269 29.688 ;
     RECT  11.269 29.088 11.293 30.024 ;
     RECT  11.293 23.328 11.377 23.352 ;
     RECT  11.293 29.088 11.377 30.12 ;
     RECT  11.173 26.448 11.405 26.76 ;
     RECT  11.405 26.736 11.449 26.76 ;
     RECT  9.605 11.952 11.513 13.08 ;
     RECT  11.045 14.208 11.513 14.472 ;
     RECT  11.257 21.168 11.549 22.2 ;
     RECT  9.683 18.288 11.749 20.136 ;
     RECT  11.549 21.168 11.749 21.576 ;
     RECT  11.749 18.288 11.804 21.576 ;
     RECT  11.804 18.192 11.891 21.576 ;
     RECT  11.513 12.336 11.945 13.08 ;
     RECT  11.185 25.104 12.133 25.128 ;
     RECT  12.133 25.104 12.409 25.656 ;
     RECT  11.377 29.088 12.413 29.736 ;
     RECT  12.413 29.088 12.484 29.688 ;
     RECT  12.409 25.104 12.589 26.232 ;
     RECT  11.189 27.936 12.589 27.96 ;
     RECT  12.589 25.104 12.709 27.96 ;
     RECT  12.484 29.04 12.709 29.688 ;
     RECT  11.891 18.432 13.057 21.576 ;
     RECT  12.661 22.8 13.093 22.824 ;
     RECT  12.757 23.904 13.093 23.928 ;
     RECT  12.709 25.104 13.093 29.688 ;
     RECT  13.093 22.8 13.205 29.688 ;
     RECT  8.104 6.816 13.208 6.84 ;
     RECT  11.945 13.056 13.208 13.08 ;
     RECT  11.513 14.448 13.208 14.472 ;
     RECT  10.825 16.368 13.208 17.208 ;
     RECT  13.057 18.432 13.208 21.72 ;
     RECT  13.205 22.8 13.208 29.112 ;
     RECT  13.208 2.148 13.312 29.112 ;
     RECT  13.312 2.418 13.504 29.112 ;
     RECT  13.504 18.432 13.709 21.432 ;
     RECT  13.504 13.056 13.715 13.08 ;
     RECT  13.504 14.448 13.715 14.472 ;
     RECT  13.504 24.48 14.177 25.704 ;
     RECT  14.177 24.48 14.249 24.504 ;
     RECT  14.177 25.68 14.285 25.704 ;
     RECT  13.709 18.432 14.357 20.616 ;
     RECT  13.504 22.8 14.501 23.4 ;
     RECT  14.357 18.432 14.537 20.136 ;
     RECT  13.504 27.312 14.537 29.112 ;
     RECT  13.504 16.368 14.645 17.208 ;
     RECT  14.537 18.768 14.681 20.136 ;
     RECT  14.501 22.8 14.753 22.824 ;
     RECT  14.705 26.208 14.789 26.232 ;
     RECT  14.537 27.312 14.797 28.488 ;
     RECT  13.504 6.768 14.821 6.84 ;
     RECT  14.797 27.936 14.825 28.488 ;
     RECT  14.681 18.768 14.969 19.368 ;
     RECT  14.969 18.768 15.113 19.272 ;
     RECT  15.113 18.768 15.149 18.792 ;
     RECT  14.825 27.984 15.185 28.488 ;
     RECT  14.821 5.808 15.221 6.84 ;
     RECT  15.185 27.984 15.257 28.44 ;
     RECT  14.645 17.184 15.401 17.208 ;
     RECT  15.257 27.984 15.401 28.008 ;
     RECT  15.541 5.712 16.333 5.736 ;
     RECT  15.221 6.768 16.333 6.84 ;
     RECT  14.713 9.312 16.441 9.336 ;
     RECT  16.441 9.312 16.553 9.528 ;
     RECT  16.333 5.712 16.621 6.84 ;
     RECT  16.621 4.992 16.748 6.84 ;
     RECT  16.748 4.896 16.789 6.84 ;
     RECT  13.504 10.848 16.801 10.872 ;
     RECT  16.789 4.896 16.835 7.416 ;
     RECT  16.553 9.504 16.841 9.528 ;
     RECT  16.801 10.656 16.94 10.872 ;
     RECT  16.513 11.952 16.945 11.976 ;
     RECT  16.94 9.744 16.981 10.872 ;
     RECT  16.945 11.952 16.981 12.312 ;
     RECT  16.835 4.992 17.027 7.416 ;
     RECT  16.981 9.744 17.027 12.312 ;
     RECT  17.027 10.32 17.089 12.312 ;
     RECT  17.027 7.392 17.129 7.416 ;
     RECT  16.789 3.408 17.165 3.432 ;
     RECT  16.513 13.44 17.629 13.464 ;
     RECT  17.089 10.32 17.737 12.36 ;
     RECT  17.629 13.392 17.737 13.464 ;
     RECT  17.737 10.32 18.205 13.464 ;
     RECT  17.557 15.024 18.205 15.048 ;
     RECT  17.027 4.992 18.565 5.832 ;
     RECT  18.565 4.128 18.608 5.832 ;
     RECT  17.881 8.976 18.608 9 ;
     RECT  18.205 10.32 18.608 15.048 ;
     RECT  18.608 2.148 18.712 28.092 ;
     RECT  18.712 2.418 18.904 27.822 ;
     RECT  18.904 2.88 19.037 2.904 ;
     RECT  18.904 3.936 19.043 8.28 ;
     RECT  19.043 3.936 19.073 7.416 ;
     RECT  19.073 3.936 19.361 6.312 ;
     RECT  18.904 10.32 19.397 12.36 ;
     RECT  19.361 4.512 19.505 6.312 ;
     RECT  19.073 7.392 19.577 7.416 ;
     RECT  18.904 13.392 19.793 14.136 ;
     RECT  19.505 5.856 20.401 6.312 ;
     RECT  20.185 8.544 20.485 8.568 ;
     RECT  20.485 7.872 20.531 8.568 ;
     RECT  19.397 10.32 20.765 11.928 ;
     RECT  20.401 5.856 20.861 6.696 ;
     RECT  20.861 5.856 20.876 6.888 ;
     RECT  20.531 7.872 20.876 8.52 ;
     RECT  19.793 13.392 20.917 13.416 ;
     RECT  20.876 5.856 20.963 8.52 ;
     RECT  20.765 10.32 20.963 11.736 ;
     RECT  20.917 13.392 21.017 14.28 ;
     RECT  20.963 10.32 21.125 11.304 ;
     RECT  21.017 13.392 21.265 13.416 ;
     RECT  20.963 5.856 21.881 6.792 ;
     RECT  20.963 8.208 22.021 8.52 ;
     RECT  22.021 8.208 22.201 9.24 ;
     RECT  21.125 10.32 22.345 11.208 ;
     RECT  22.345 10.32 22.417 11.928 ;
     RECT  21.265 13.056 22.417 13.416 ;
     RECT  19.505 4.512 22.529 4.536 ;
     RECT  22.201 8.112 22.556 9.24 ;
     RECT  22.417 10.32 22.556 13.416 ;
     RECT  21.881 5.856 22.561 6.696 ;
     RECT  22.201 14.976 22.669 15 ;
     RECT  22.556 8.112 22.817 13.416 ;
     RECT  22.669 14.832 22.817 15 ;
     RECT  22.817 10.224 22.961 13.416 ;
     RECT  22.817 14.832 23.353 14.856 ;
     RECT  22.561 5.712 23.569 6.696 ;
     RECT  23.569 5.184 23.677 6.696 ;
     RECT  22.817 8.112 23.677 9.24 ;
     RECT  23.749 3.024 23.821 3.048 ;
     RECT  23.821 2.832 24.008 3.048 ;
     RECT  23.677 5.184 24.008 9.24 ;
     RECT  22.961 10.32 24.008 13.416 ;
     RECT  23.353 14.736 24.008 14.856 ;
     RECT  24.008 2.148 24.112 28.092 ;
     RECT  24.112 2.418 24.304 27.822 ;
     RECT  24.304 8.976 24.509 14.76 ;
     RECT  24.304 2.736 25.297 3.48 ;
     RECT  24.304 4.608 25.297 5.064 ;
     RECT  24.304 6.24 25.297 7.8 ;
     RECT  24.509 12.384 25.333 14.76 ;
     RECT  24.509 8.976 25.441 11.352 ;
     RECT  25.333 12.384 25.549 15.096 ;
     RECT  25.297 4.608 25.657 7.8 ;
     RECT  25.441 8.928 25.657 11.352 ;
     RECT  25.297 2.592 25.729 3.48 ;
     RECT  25.657 4.608 25.729 11.352 ;
     RECT  25.549 12.336 25.801 15.096 ;
     RECT  25.729 2.592 26.125 11.352 ;
     RECT  25.801 12.336 26.125 15.24 ;
     RECT  26.125 2.592 26.273 15.24 ;
     RECT  26.273 2.736 26.387 15.24 ;
     RECT  26.305 18.24 26.389 18.264 ;
     RECT  26.387 15.072 26.449 15.24 ;
     RECT  26.449 15.072 26.849 16.056 ;
     RECT  26.387 2.736 26.921 13.608 ;
     RECT  26.917 16.704 27.209 16.728 ;
     RECT  26.921 12.336 27.395 13.608 ;
     RECT  26.849 15.072 27.425 15.432 ;
     RECT  27.395 13.584 27.493 13.608 ;
     RECT  27.457 14.832 27.493 14.856 ;
     RECT  27.493 13.584 27.641 14.856 ;
     RECT  26.921 2.736 27.925 11.352 ;
     RECT  27.395 12.336 27.925 12.456 ;
     RECT  27.925 2.736 28.501 12.456 ;
     RECT  27.641 13.584 28.501 14.808 ;
     RECT  28.501 2.736 28.645 14.808 ;
     RECT  28.645 2.736 29.077 15.144 ;
     RECT  29.077 2.736 30.06 15.24 ;
     RECT  30.06 2.736 30.089 2.76 ;
    LAYER M5 ;
     RECT  2.4 2.137 2.52 2.151 ;
     RECT  7.8 2.137 7.92 2.151 ;
     RECT  13.2 2.137 13.32 2.151 ;
     RECT  18.6 2.137 18.72 2.151 ;
     RECT  24 2.137 24.12 2.151 ;
     RECT  2.4 2.151 2.712 2.389 ;
     RECT  2.4 2.389 2.808 2.485 ;
     RECT  2.304 2.485 2.808 3.925 ;
     RECT  2.304 3.925 2.856 4.357 ;
     RECT  3.84 2.485 3.864 4.357 ;
     RECT  2.304 4.357 3.864 4.595 ;
     RECT  5.232 3.397 5.256 4.885 ;
     RECT  16.8 3.397 16.824 6.757 ;
     RECT  20.88 4.501 20.904 6.899 ;
     RECT  7.8 2.151 8.112 7.333 ;
     RECT  18.6 2.151 18.912 7.381 ;
     RECT  16.8 6.757 17.016 7.427 ;
     RECT  20.928 7.237 20.952 7.861 ;
     RECT  18.6 7.381 19.032 8.291 ;
     RECT  20.496 7.861 20.952 8.579 ;
     RECT  5.232 4.885 6.168 8.869 ;
     RECT  7.488 7.333 8.112 8.869 ;
     RECT  5.232 8.869 8.112 9.109 ;
     RECT  5.136 9.109 8.112 9.349 ;
     RECT  22.608 9.397 22.632 10.259 ;
     RECT  4.992 9.349 8.112 10.789 ;
     RECT  13.2 2.151 13.512 10.837 ;
     RECT  16.992 7.427 17.016 11.651 ;
     RECT  2.304 4.595 3 12.949 ;
     RECT  1.008 13.045 1.032 13.189 ;
     RECT  0.288 13.189 1.032 13.379 ;
     RECT  4.608 10.789 8.112 13.523 ;
     RECT  20.928 8.579 20.952 14.291 ;
     RECT  5.04 13.523 8.112 14.437 ;
     RECT  13.2 10.837 13.704 14.483 ;
     RECT  5.04 14.437 8.328 14.723 ;
     RECT  5.04 14.723 8.112 14.773 ;
     RECT  27.36 13.381 27.384 15.443 ;
     RECT  4.896 14.773 8.112 15.683 ;
     RECT  4.944 15.683 8.112 17.317 ;
     RECT  4.944 17.317 8.232 17.605 ;
     RECT  4.944 17.605 9.528 18.037 ;
     RECT  26.352 14.197 26.376 18.275 ;
     RECT  13.2 14.483 13.512 18.469 ;
     RECT  4.944 18.037 9.672 19.283 ;
     RECT  11.856 18.181 11.88 19.379 ;
     RECT  4.944 19.283 9.528 20.147 ;
     RECT  11.184 19.909 11.208 21.013 ;
     RECT  2.304 12.949 3.336 21.155 ;
     RECT  4.944 20.147 8.952 21.155 ;
     RECT  11.184 21.013 11.784 21.443 ;
     RECT  11.76 21.443 11.784 21.587 ;
     RECT  5.328 21.155 8.952 21.683 ;
     RECT  2.304 21.155 2.808 21.731 ;
     RECT  5.328 21.683 5.352 22.259 ;
     RECT  13.2 18.469 13.608 22.835 ;
     RECT  6.336 21.683 8.952 23.317 ;
     RECT  9.936 22.645 9.96 23.317 ;
     RECT  2.4 21.731 2.808 23.603 ;
     RECT  6.336 23.317 9.96 23.893 ;
     RECT  13.2 22.835 13.512 23.893 ;
     RECT  12.768 23.893 13.512 24.469 ;
     RECT  14.736 18.757 14.76 24.469 ;
     RECT  5.088 22.789 5.112 25.045 ;
     RECT  6.096 23.893 9.96 25.045 ;
     RECT  11.328 23.317 11.352 25.621 ;
     RECT  12.768 24.469 14.76 25.621 ;
     RECT  11.328 25.621 14.76 26.243 ;
     RECT  11.328 26.243 14.088 26.437 ;
     RECT  4.272 25.045 9.96 26.677 ;
     RECT  3.888 26.677 9.96 27.301 ;
     RECT  11.184 26.437 14.088 27.301 ;
     RECT  2.4 23.603 2.712 27.925 ;
     RECT  3.888 27.301 14.76 27.925 ;
     RECT  2.4 27.925 14.76 27.973 ;
     RECT  18.6 8.291 18.912 28.089 ;
     RECT  24 2.151 24.312 28.089 ;
     RECT  2.4 27.973 14.856 28.103 ;
     RECT  18.6 28.089 18.72 28.103 ;
     RECT  24 28.089 24.12 28.103 ;
     RECT  3.12 28.103 14.856 28.357 ;
     RECT  3.12 28.357 15.048 28.405 ;
     RECT  3.12 28.405 15.24 29.653 ;
     RECT  3.024 29.653 15.24 30.096 ;
     RECT  11.328 30.096 11.352 30.131 ;
     RECT  2.808 2.485 3.84 3.925 ;
     RECT  3.864 3.397 5.232 4.595 ;
     RECT  2.856 3.925 3.84 4.357 ;
     RECT  20.88 6.899 20.904 7.237 ;
     RECT  20.88 7.237 20.928 7.861 ;
     RECT  6.168 7.333 7.488 8.869 ;
     RECT  19.032 7.861 20.496 8.291 ;
     RECT  22.632 9.397 24 10.259 ;
     RECT  3.336 12.949 4.608 13.523 ;
     RECT  1.032 13.045 2.304 13.331 ;
     RECT  1.08 13.331 2.304 13.379 ;
     RECT  4.896 13.523 5.04 14.773 ;
     RECT  26.376 14.197 27.36 15.443 ;
     RECT  11.88 18.181 13.2 19.379 ;
     RECT  13.608 18.757 14.736 22.835 ;
     RECT  11.784 21.013 13.2 21.587 ;
     RECT  5.352 21.683 6.336 22.259 ;
     RECT  5.328 22.259 6.336 22.789 ;
     RECT  8.952 22.645 9.936 23.317 ;
     RECT  5.112 22.789 6.336 23.893 ;
     RECT  13.512 22.835 14.736 24.469 ;
     RECT  9.96 23.317 11.328 26.437 ;
     RECT  5.112 23.893 6.096 25.045 ;
     RECT  11.352 23.893 12.768 25.621 ;
     RECT  14.088 26.243 14.76 27.301 ;
     RECT  9.96 26.437 11.184 27.301 ;
     RECT  2.712 26.677 3.888 27.925 ;
  END
END ot_smh_tr_w128_s2_m0
END LIBRARY
